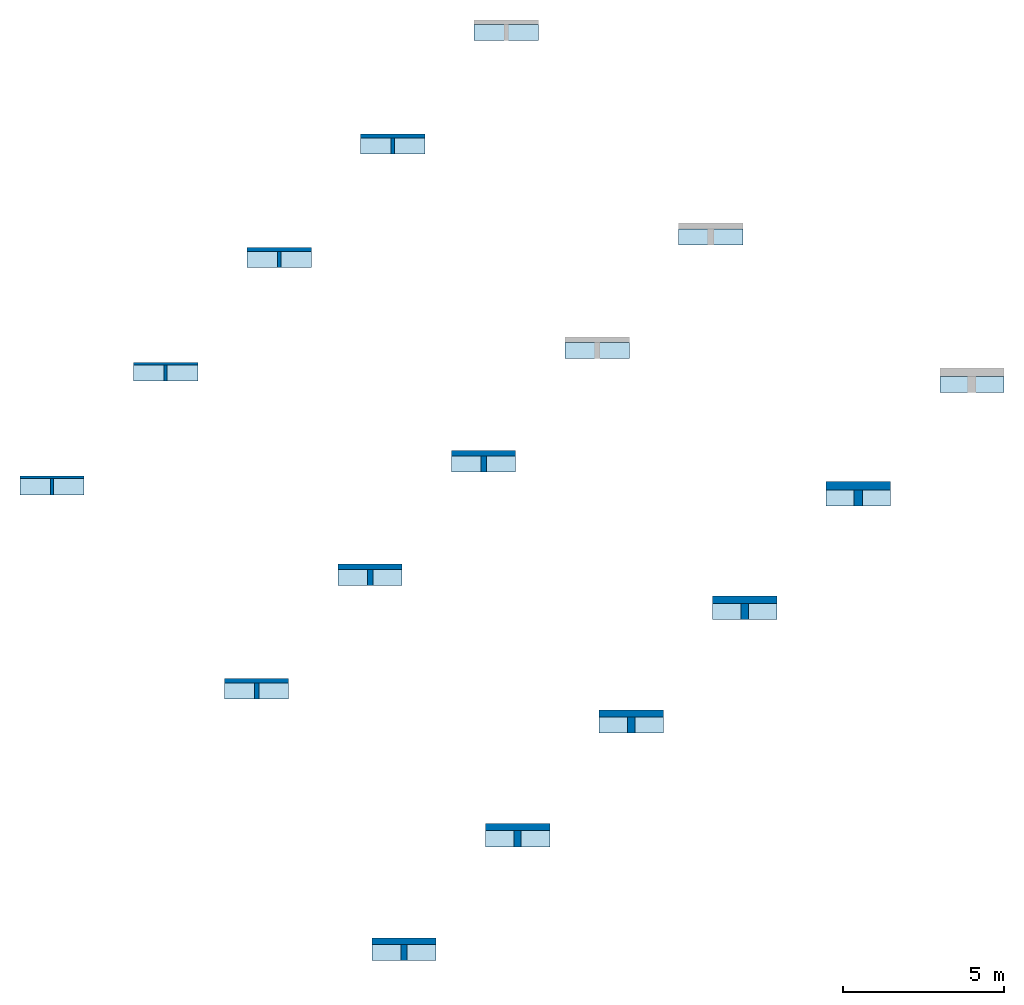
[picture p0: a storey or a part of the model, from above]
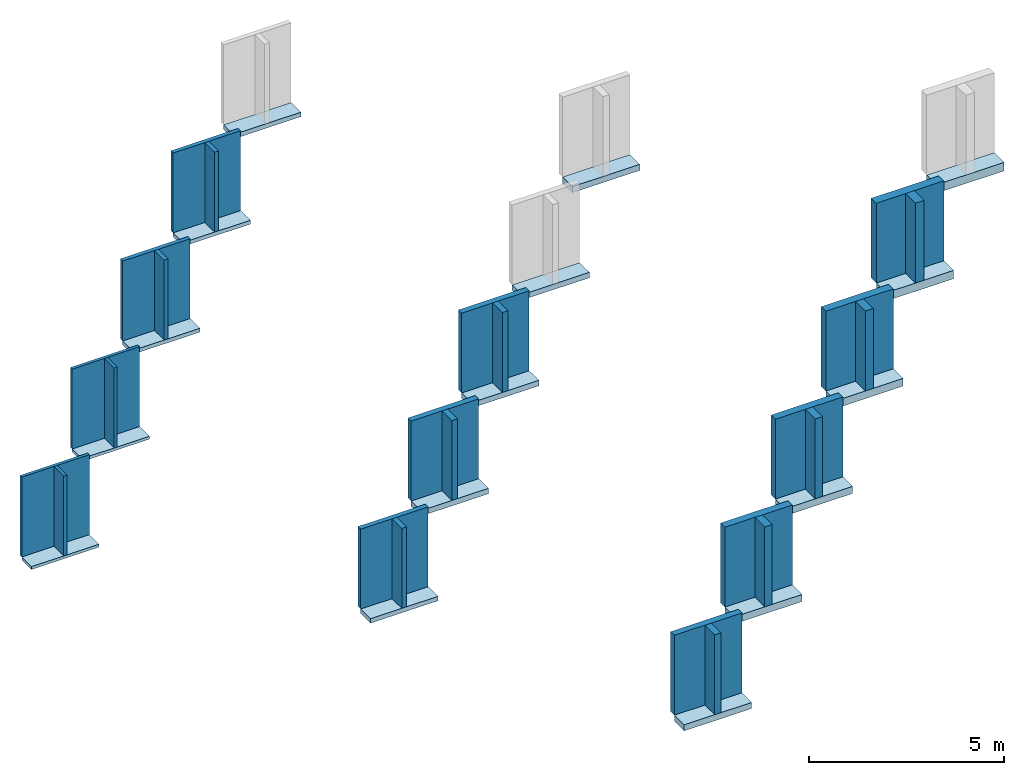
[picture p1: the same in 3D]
Properties of the parts of a building model (IFC2X3), part 1 of 3

# File
Description: ViewDefinition [CoordinationView_V2.0, QuantityTakeOffAddOnView]
Time: 2021-05-19T20:18:22
Written by: The EXPRESS Data Manager Version 5.02.0100.07 : 28 Aug 2013
Made in: 20190108_1515(x64) - Exporter 19.1.0.0 - Alternate UI 19.1.0.0
Comment: STEP Physical File produced by: The EXPRESS Data Manager Version 5.02.0100.07 : 28 Aug 2013 * Module: EDMstepFileFactory/EDMstandAlone * Creation date: Wed May 19 20:18:22 2021 * Host: lt-026 * Database: C:\Users\WF2BF~1.POE\AppData\Local\Temp\{9F13D511-4A9E-4208-AD03-301C394EC26A}\ifc * Database version: 5507 * Database creation date: Wed May 19 20:18:21 2021 * Schema: IFC2X3 * Model: DataRepository.ifc * Model creation date: Wed May 19 20:18:21 2021 * Header model: DataRepository.ifc_HeaderModel * Header model creation date: Wed May 19 20:18:21 2021 * EDMuser: sdai-user * EDMgroup: sdai-group * License ID and type: 5605 : Permanent license. Expiry date: * EDMstepFileFactory options: 020000

# IfcSite, Default
RefLatitude: 42, 24, 53, 508911; RefLongitude: -71, -15, -29, -58837; RefElevation: 0 mm
Other - Category: Project Information

# IfcBuilding
Pset_BuildingCommon - NumberOfStoreys: 2
Pset_ProductRequirements - Category: Project Information; sets with these values: 2

# IfcBuildingStorey: Level:Level 1, Begane grond
LongName: Begane grond; Elevation: 0 mm
Pset_AirSideSystemInformation - Name: Begane grond
Pset_ProductRequirements - Name: Begane grond; Category: Levels
Constraints - Elevation: 0 mm
Dimensions - Computation Height: 0 mm
Identity Data - Structural: no; Building Story: yes; Name: Begane grond
Other - Category: Levels; Family: Level: Level 1; Family and Type: Level: Level 1; Type: Level: Level 1; Type Id: Level: Level 1
Constraints(Type) - Elevation Base: Project Base Point
Graphics(Type) - Color: 0; Line Pattern: Solid; Line Weight: 1; Symbol at End 1 Default: no; Symbol at End 2 Default: yes
Identity Data(Type) - Type Name: Level 1
Other(Type) - Category: Levels; Family Name: Level

# IfcBuildingStorey: Level:NL_00_niveau, Lengte
LongName: Lengte; Elevation: 2500 mm
Other(Type) - Category: Levels; Family Name: Level
Pset_AirSideSystemInformation - Name: Lengte
Pset_ProductRequirements - Name: Lengte; Category: Levels
Constraints - Elevation: 2500 mm
Dimensions - Computation Height: 0 mm
Identity Data - Structural: no; Building Story: yes; Name: Lengte
Other - Category: Levels; Family: Level: NL_00_niveau; Family and Type: Level: NL_00_niveau; Type: Level: NL_00_niveau; Type Id: Level: NL_00_niveau
Constraints(Type) - Elevation Base: Project Base Point
Graphics(Type) - Line Weight: 1; Symbol at End 1 Default: no; Symbol at End 2 Default: yes; Color: 16711680; Line Pattern: NL_00_niveau; Symbol: NLRS_00_LAB_niveau bovenkant_gen_cadix: 1.8mm
Identity Data(Type) - Type Name: NL_00_niveau

# IfcRoof: Basic Roof:NLRS_27_RO_Naturoll 037_120x380x6500mm, Basic Roof:NLRS_27_RO_Naturoll 037_120x380x6500mm:13041
In: Lengte
Classification: 27 Daken (Uniformat)
Pset_ElementShading - Roughness: 304.8 mm
Pset_ManufacturerTypeInformation - Manufacturer: Knauf Insulation B.V.
Pset_ProductRequirements - Category: Roofs
Pset_QuantityTakeOff - Reference: NLRS_27_RO_Naturoll 037_120x380x6500mm
Pset_RoofCommon - IsExternal: yes; Reference: NLRS_27_RO_Naturoll 037_120x380x6500mm; ProjectedArea: 1 m2; TotalArea: 1 m2
Constraints - Related to Mass: no; Room Bounding: yes; Base Level: Level: Lengte; Base Offset From Level: 0 mm; Cutoff Offset: 0 mm
Construction - Fascia Depth: 0 mm; Rafter Cut: Plumb Cut; Maximum Ridge Height: 2620 mm
Dimensions - Area: 1 m2; Thickness: 120 mm; Volume: 0.12 m3
Other - Category: Roofs; Family: Basic Roof: NLRS_27_RO_Naturoll 037_120x380x6500mm; Family and Type: Basic Roof: NLRS_27_RO_Naturoll 037_120x380x6500mm; Type: Basic Roof: NLRS_27_RO_Naturoll 037_120x380x6500mm; Type Id: Basic Roof: NLRS_27_RO_Naturoll 037_120x380x6500mm
Phasing - Phase Created: New Construction
Analytical Properties(Type) - Roughness: 1; Thermal mass: 0; Absorptance: 0.1; Heat Transfer Coefficient (U): 0.291667; Thermal Resistance (R): 3.42857
Construction(Type) - Default Thickness: 120 mm
Graphics(Type) - Coarse Scale Fill Color: 0
Identity Data(Type) - Type Image: Raster image: Naturoll 037.jpg (3); Assembly Code: 27; Assembly Description: Daken; Description: Naturoll 037 - 120mm; Manufacturer: Knauf Insulation B.V.; Model: Naturoll 037 is een onbeklede glaswoldeken met ECOSE® Technology; Type Name: NLRS_27_RO_Naturoll 037_120x380x6500mm; URL: www.knaufinsulation.nl
Other(Type) - Category: Roofs; Family Name: Basic Roof

# IfcRoof: Basic Roof:NLRS_27_RO_Naturoll 037_120x580x6500mm, Basic Roof:NLRS_27_RO_Naturoll 037_120x580x6500mm:13066
In: Lengte
Classification: 27 Daken (Uniformat)
Pset_ElementShading - Roughness: 304.8 mm
Pset_ManufacturerTypeInformation - Manufacturer: Knauf Insulation B.V.
Pset_ProductRequirements - Category: Roofs
Pset_QuantityTakeOff - Reference: NLRS_27_RO_Naturoll 037_120x580x6500mm
Pset_RoofCommon - IsExternal: yes; Reference: NLRS_27_RO_Naturoll 037_120x580x6500mm; ProjectedArea: 1 m2; TotalArea: 1 m2
Constraints - Related to Mass: no; Room Bounding: yes; Base Level: Level: Lengte; Base Offset From Level: 0 mm; Cutoff Offset: 0 mm
Construction - Fascia Depth: 0 mm; Rafter Cut: Plumb Cut; Maximum Ridge Height: 2620 mm
Dimensions - Area: 1 m2; Thickness: 120 mm; Volume: 0.12 m3
Other - Category: Roofs; Family: Basic Roof: NLRS_27_RO_Naturoll 037_120x580x6500mm; Family and Type: Basic Roof: NLRS_27_RO_Naturoll 037_120x580x6500mm; Type: Basic Roof: NLRS_27_RO_Naturoll 037_120x580x6500mm; Type Id: Basic Roof: NLRS_27_RO_Naturoll 037_120x580x6500mm
Phasing - Phase Created: New Construction
Analytical Properties(Type) - Roughness: 1; Thermal mass: 0; Absorptance: 0.1; Heat Transfer Coefficient (U): 0.291667; Thermal Resistance (R): 3.42857
Construction(Type) - Default Thickness: 120 mm
Graphics(Type) - Coarse Scale Fill Color: 0
Identity Data(Type) - Type Image: Raster image: Naturoll 037.jpg (3); Assembly Code: 27; Assembly Description: Daken; Description: Naturoll 037 - 120mm; Manufacturer: Knauf Insulation B.V.; Model: Naturoll 037 is een onbeklede glaswoldeken met ECOSE® Technology; Type Name: NLRS_27_RO_Naturoll 037_120x580x6500mm; URL: www.knaufinsulation.nl
Other(Type) - Category: Roofs; Family Name: Basic Roof

# IfcRoof: Basic Roof:NLRS_27_RO_Naturoll 037_140x380x5600mm, Basic Roof:NLRS_27_RO_Naturoll 037_140x380x5600mm:13091
In: Lengte
Classification: 27 Daken (Uniformat)
Pset_ElementShading - Roughness: 304.8 mm
Pset_ManufacturerTypeInformation - Manufacturer: Knauf Insulation B.V.
Pset_ProductRequirements - Category: Roofs
Pset_QuantityTakeOff - Reference: NLRS_27_RO_Naturoll 037_140x380x5600mm
Pset_RoofCommon - IsExternal: yes; Reference: NLRS_27_RO_Naturoll 037_140x380x5600mm; ProjectedArea: 1 m2; TotalArea: 1 m2
Constraints - Related to Mass: no; Room Bounding: yes; Base Level: Level: Lengte; Base Offset From Level: 0 mm; Cutoff Offset: 0 mm
Construction - Fascia Depth: 0 mm; Rafter Cut: Plumb Cut; Maximum Ridge Height: 2640 mm
Dimensions - Area: 1 m2; Thickness: 140 mm; Volume: 0.14 m3
Other - Category: Roofs; Family: Basic Roof: NLRS_27_RO_Naturoll 037_140x380x5600mm; Family and Type: Basic Roof: NLRS_27_RO_Naturoll 037_140x380x5600mm; Type: Basic Roof: NLRS_27_RO_Naturoll 037_140x380x5600mm; Type Id: Basic Roof: NLRS_27_RO_Naturoll 037_140x380x5600mm
Phasing - Phase Created: New Construction
Analytical Properties(Type) - Roughness: 1; Thermal mass: 0; Thermal Resistance (R): 4; Absorptance: 0.1; Heat Transfer Coefficient (U): 0.25
Construction(Type) - Default Thickness: 140 mm
Graphics(Type) - Coarse Scale Fill Color: 0
Identity Data(Type) - Type Image: Raster image: Naturoll 037.jpg (3); Assembly Code: 27; Assembly Description: Daken; Description: Naturoll 037 - 140mm; Manufacturer: Knauf Insulation B.V.; Model: Naturoll 037 is een onbeklede glaswoldeken met ECOSE® Technology; Type Name: NLRS_27_RO_Naturoll 037_140x380x5600mm; URL: www.knaufinsulation.nl
Other(Type) - Category: Roofs; Family Name: Basic Roof

# IfcRoof: Basic Roof:NLRS_27_RO_Naturoll 037_140x580x5600mm, Basic Roof:NLRS_27_RO_Naturoll 037_140x580x5600mm:13324
In: Lengte
Classification: 27 Daken (Uniformat)
Pset_ElementShading - Roughness: 304.8 mm
Pset_ManufacturerTypeInformation - Manufacturer: Knauf Insulation B.V.
Pset_ProductRequirements - Category: Roofs
Pset_QuantityTakeOff - Reference: NLRS_27_RO_Naturoll 037_140x580x5600mm
Pset_RoofCommon - IsExternal: yes; Reference: NLRS_27_RO_Naturoll 037_140x580x5600mm; ProjectedArea: 1 m2; TotalArea: 1 m2
Constraints - Related to Mass: no; Room Bounding: yes; Base Level: Level: Lengte; Base Offset From Level: 0 mm; Cutoff Offset: 0 mm
Construction - Fascia Depth: 0 mm; Rafter Cut: Plumb Cut; Maximum Ridge Height: 2640 mm
Dimensions - Area: 1 m2; Thickness: 140 mm; Volume: 0.14 m3
Other - Category: Roofs; Family: Basic Roof: NLRS_27_RO_Naturoll 037_140x580x5600mm; Family and Type: Basic Roof: NLRS_27_RO_Naturoll 037_140x580x5600mm; Type: Basic Roof: NLRS_27_RO_Naturoll 037_140x580x5600mm; Type Id: Basic Roof: NLRS_27_RO_Naturoll 037_140x580x5600mm
Phasing - Phase Created: New Construction
Analytical Properties(Type) - Roughness: 1; Thermal mass: 0; Thermal Resistance (R): 4; Absorptance: 0.1; Heat Transfer Coefficient (U): 0.25
Construction(Type) - Default Thickness: 140 mm
Graphics(Type) - Coarse Scale Fill Color: 0
Identity Data(Type) - Type Image: Raster image: Naturoll 037.jpg (3); Assembly Code: 27; Assembly Description: Daken; Description: Naturoll 037 - 140mm; Manufacturer: Knauf Insulation B.V.; Model: Naturoll 037 is een onbeklede glaswoldeken met ECOSE® Technology; Type Name: NLRS_27_RO_Naturoll 037_140x580x5600mm; URL: www.knaufinsulation.nl
Other(Type) - Category: Roofs; Family Name: Basic Roof

# IfcRoof: Basic Roof:NLRS_27_RO_Naturoll 037_170x380x4600mm, Basic Roof:NLRS_27_RO_Naturoll 037_170x380x4600mm:13346
In: Lengte
Classification: 27 Daken (Uniformat)
Pset_ElementShading - Roughness: 304.8 mm
Pset_ManufacturerTypeInformation - Manufacturer: Knauf Insulation B.V.
Pset_ProductRequirements - Category: Roofs
Pset_QuantityTakeOff - Reference: NLRS_27_RO_Naturoll 037_170x380x4600mm
Pset_RoofCommon - IsExternal: yes; Reference: NLRS_27_RO_Naturoll 037_170x380x4600mm; ProjectedArea: 1 m2; TotalArea: 1 m2
Constraints - Related to Mass: no; Room Bounding: yes; Base Level: Level: Lengte; Base Offset From Level: 0 mm; Cutoff Offset: 0 mm
Construction - Fascia Depth: 0 mm; Rafter Cut: Plumb Cut; Maximum Ridge Height: 2670 mm
Dimensions - Area: 1 m2; Thickness: 170 mm; Volume: 0.17 m3
Other - Category: Roofs; Family: Basic Roof: NLRS_27_RO_Naturoll 037_170x380x4600mm; Family and Type: Basic Roof: NLRS_27_RO_Naturoll 037_170x380x4600mm; Type: Basic Roof: NLRS_27_RO_Naturoll 037_170x380x4600mm; Type Id: Basic Roof: NLRS_27_RO_Naturoll 037_170x380x4600mm
Phasing - Phase Created: New Construction
Analytical Properties(Type) - Roughness: 1; Thermal mass: 0; Absorptance: 0.1; Heat Transfer Coefficient (U): 0.205882; Thermal Resistance (R): 4.85714
Construction(Type) - Default Thickness: 170 mm
Graphics(Type) - Coarse Scale Fill Color: 0
Identity Data(Type) - Type Image: Raster image: Naturoll 037.jpg (3); Assembly Code: 27; Assembly Description: Daken; Description: Naturoll 037 - 170mm; Manufacturer: Knauf Insulation B.V.; Model: Naturoll 037 is een onbeklede glaswoldeken met ECOSE® Technology; Type Name: NLRS_27_RO_Naturoll 037_170x380x4600mm; URL: www.knaufinsulation.nl
Other(Type) - Category: Roofs; Family Name: Basic Roof

# IfcRoof: Basic Roof:NLRS_27_RO_Naturoll 037_170x580x4600mm, Basic Roof:NLRS_27_RO_Naturoll 037_170x580x4600mm:13368
In: Lengte
Classification: 27 Daken (Uniformat)
Pset_ElementShading - Roughness: 304.8 mm
Pset_ManufacturerTypeInformation - Manufacturer: Knauf Insulation B.V.
Pset_ProductRequirements - Category: Roofs
Pset_QuantityTakeOff - Reference: NLRS_27_RO_Naturoll 037_170x580x4600mm
Pset_RoofCommon - IsExternal: yes; Reference: NLRS_27_RO_Naturoll 037_170x580x4600mm; ProjectedArea: 1 m2; TotalArea: 1 m2
Constraints - Related to Mass: no; Room Bounding: yes; Base Level: Level: Lengte; Base Offset From Level: 0 mm; Cutoff Offset: 0 mm
Construction - Fascia Depth: 0 mm; Rafter Cut: Plumb Cut; Maximum Ridge Height: 2670 mm
Dimensions - Area: 1 m2; Thickness: 170 mm; Volume: 0.17 m3
Other - Category: Roofs; Family: Basic Roof: NLRS_27_RO_Naturoll 037_170x580x4600mm; Family and Type: Basic Roof: NLRS_27_RO_Naturoll 037_170x580x4600mm; Type: Basic Roof: NLRS_27_RO_Naturoll 037_170x580x4600mm; Type Id: Basic Roof: NLRS_27_RO_Naturoll 037_170x580x4600mm
Phasing - Phase Created: New Construction
Analytical Properties(Type) - Roughness: 1; Thermal mass: 0; Absorptance: 0.1; Heat Transfer Coefficient (U): 0.205882; Thermal Resistance (R): 4.85714
Construction(Type) - Default Thickness: 170 mm
Graphics(Type) - Coarse Scale Fill Color: 0
Identity Data(Type) - Type Image: Raster image: Naturoll 037.jpg (3); Assembly Code: 27; Assembly Description: Daken; Description: Naturoll 037 - 170mm; Manufacturer: Knauf Insulation B.V.; Model: Naturoll 037 is een onbeklede glaswoldeken met ECOSE® Technology; Type Name: NLRS_27_RO_Naturoll 037_170x580x4600mm; URL: www.knaufinsulation.nl
Other(Type) - Category: Roofs; Family Name: Basic Roof

# IfcRoof: Basic Roof:NLRS_27_RO_Naturoll 037_170x590x4600mm, Basic Roof:NLRS_27_RO_Naturoll 037_170x590x4600mm:13390
In: Lengte
Classification: 27 Daken (Uniformat)
Pset_ElementShading - Roughness: 304.8 mm
Pset_ManufacturerTypeInformation - Manufacturer: Knauf Insulation B.V.
Pset_ProductRequirements - Category: Roofs
Pset_QuantityTakeOff - Reference: NLRS_27_RO_Naturoll 037_170x590x4600mm
Pset_RoofCommon - IsExternal: yes; Reference: NLRS_27_RO_Naturoll 037_170x590x4600mm; ProjectedArea: 1 m2; TotalArea: 1 m2
Constraints - Related to Mass: no; Room Bounding: yes; Base Level: Level: Lengte; Base Offset From Level: 0 mm; Cutoff Offset: 0 mm
Construction - Fascia Depth: 0 mm; Rafter Cut: Plumb Cut; Maximum Ridge Height: 2670 mm
Dimensions - Area: 1 m2; Thickness: 170 mm; Volume: 0.17 m3
Other - Category: Roofs; Family: Basic Roof: NLRS_27_RO_Naturoll 037_170x590x4600mm; Family and Type: Basic Roof: NLRS_27_RO_Naturoll 037_170x590x4600mm; Type: Basic Roof: NLRS_27_RO_Naturoll 037_170x590x4600mm; Type Id: Basic Roof: NLRS_27_RO_Naturoll 037_170x590x4600mm
Phasing - Phase Created: New Construction
Analytical Properties(Type) - Roughness: 1; Thermal mass: 0; Absorptance: 0.1; Heat Transfer Coefficient (U): 0.205882; Thermal Resistance (R): 4.85714
Construction(Type) - Default Thickness: 170 mm
Graphics(Type) - Coarse Scale Fill Color: 0
Identity Data(Type) - Type Image: Raster image: Naturoll 037.jpg (3); Assembly Code: 27; Assembly Description: Daken; Description: Naturoll 037 - 170mm; Manufacturer: Knauf Insulation B.V.; Model: Naturoll 037 is een onbeklede glaswoldeken met ECOSE® Technology; Type Name: NLRS_27_RO_Naturoll 037_170x590x4600mm; URL: www.knaufinsulation.nl
Other(Type) - Category: Roofs; Family Name: Basic Roof

# IfcRoof: Basic Roof:NLRS_27_RO_Naturoll 037_190x380x4100mm, Basic Roof:NLRS_27_RO_Naturoll 037_190x380x4100mm:13412
In: Lengte
Classification: 27 Daken (Uniformat)
Pset_ElementShading - Roughness: 304.8 mm
Pset_ManufacturerTypeInformation - Manufacturer: Knauf Insulation B.V.
Pset_ProductRequirements - Category: Roofs
Pset_QuantityTakeOff - Reference: NLRS_27_RO_Naturoll 037_190x380x4100mm
Pset_RoofCommon - IsExternal: yes; Reference: NLRS_27_RO_Naturoll 037_190x380x4100mm; ProjectedArea: 1 m2; TotalArea: 1 m2
Constraints - Related to Mass: no; Room Bounding: yes; Base Level: Level: Lengte; Base Offset From Level: 0 mm; Cutoff Offset: 0 mm
Construction - Fascia Depth: 0 mm; Rafter Cut: Plumb Cut; Maximum Ridge Height: 2690 mm
Dimensions - Area: 1 m2; Thickness: 190 mm; Volume: 0.19 m3
Other - Category: Roofs; Family: Basic Roof: NLRS_27_RO_Naturoll 037_190x380x4100mm; Family and Type: Basic Roof: NLRS_27_RO_Naturoll 037_190x380x4100mm; Type: Basic Roof: NLRS_27_RO_Naturoll 037_190x380x4100mm; Type Id: Basic Roof: NLRS_27_RO_Naturoll 037_190x380x4100mm
Phasing - Phase Created: New Construction
Analytical Properties(Type) - Roughness: 1; Thermal mass: 0; Absorptance: 0.1; Heat Transfer Coefficient (U): 0.184211; Thermal Resistance (R): 5.42857
Construction(Type) - Default Thickness: 190 mm
Graphics(Type) - Coarse Scale Fill Color: 0
Identity Data(Type) - Type Image: Raster image: Naturoll 037.jpg (3); Assembly Code: 27; Assembly Description: Daken; Description: Naturoll 037 - 190mm; Manufacturer: Knauf Insulation B.V.; Model: Naturoll 037 is een onbeklede glaswoldeken met ECOSE® Technology; Type Name: NLRS_27_RO_Naturoll 037_190x380x4100mm; URL: www.knaufinsulation.nl
Other(Type) - Category: Roofs; Family Name: Basic Roof

# IfcRoof: Basic Roof:NLRS_27_RO_Naturoll 037_190x590x4100mm, Basic Roof:NLRS_27_RO_Naturoll 037_190x590x4100mm:13511
In: Lengte
Classification: 27 Daken (Uniformat)
Pset_ElementShading - Roughness: 304.8 mm
Pset_ManufacturerTypeInformation - Manufacturer: Knauf Insulation B.V.
Pset_ProductRequirements - Category: Roofs
Pset_QuantityTakeOff - Reference: NLRS_27_RO_Naturoll 037_190x590x4100mm
Pset_RoofCommon - IsExternal: yes; Reference: NLRS_27_RO_Naturoll 037_190x590x4100mm; ProjectedArea: 1 m2; TotalArea: 1 m2
Constraints - Related to Mass: no; Room Bounding: yes; Base Level: Level: Lengte; Base Offset From Level: 0 mm; Cutoff Offset: 0 mm
Construction - Fascia Depth: 0 mm; Rafter Cut: Plumb Cut; Maximum Ridge Height: 2690 mm
Dimensions - Area: 1 m2; Thickness: 190 mm; Volume: 0.19 m3
Other - Category: Roofs; Family: Basic Roof: NLRS_27_RO_Naturoll 037_190x590x4100mm; Family and Type: Basic Roof: NLRS_27_RO_Naturoll 037_190x590x4100mm; Type: Basic Roof: NLRS_27_RO_Naturoll 037_190x590x4100mm; Type Id: Basic Roof: NLRS_27_RO_Naturoll 037_190x590x4100mm
Phasing - Phase Created: New Construction
Analytical Properties(Type) - Roughness: 1; Thermal mass: 0; Absorptance: 0.1; Heat Transfer Coefficient (U): 0.184211; Thermal Resistance (R): 5.42857
Construction(Type) - Default Thickness: 190 mm
Graphics(Type) - Coarse Scale Fill Color: 0
Identity Data(Type) - Type Image: Raster image: Naturoll 037.jpg (3); Assembly Code: 27; Assembly Description: Daken; Description: Naturoll 037 - 190mm; Manufacturer: Knauf Insulation B.V.; Model: Naturoll 037 is een onbeklede glaswoldeken met ECOSE® Technology; Type Name: NLRS_27_RO_Naturoll 037_190x590x4100mm; URL: www.knaufinsulation.nl
Other(Type) - Category: Roofs; Family Name: Basic Roof

# IfcRoof: Basic Roof:NLRS_27_RO_Naturoll 037_220x580x3500mm, Basic Roof:NLRS_27_RO_Naturoll 037_220x580x3500mm:13531
In: Lengte
Classification: 27 Daken (Uniformat)
Pset_ElementShading - Roughness: 304.8 mm
Pset_ManufacturerTypeInformation - Manufacturer: Knauf Insulation B.V.
Pset_ProductRequirements - Category: Roofs
Pset_QuantityTakeOff - Reference: NLRS_27_RO_Naturoll 037_220x580x3500mm
Pset_RoofCommon - IsExternal: yes; Reference: NLRS_27_RO_Naturoll 037_220x580x3500mm; ProjectedArea: 1 m2; TotalArea: 1 m2
Constraints - Related to Mass: no; Room Bounding: yes; Base Level: Level: Lengte; Base Offset From Level: 0 mm; Cutoff Offset: 0 mm
Construction - Fascia Depth: 0 mm; Rafter Cut: Plumb Cut; Maximum Ridge Height: 2720 mm
Dimensions - Area: 1 m2; Thickness: 220 mm; Volume: 0.22 m3
Other - Category: Roofs; Family: Basic Roof: NLRS_27_RO_Naturoll 037_220x580x3500mm; Family and Type: Basic Roof: NLRS_27_RO_Naturoll 037_220x580x3500mm; Type: Basic Roof: NLRS_27_RO_Naturoll 037_220x580x3500mm; Type Id: Basic Roof: NLRS_27_RO_Naturoll 037_220x580x3500mm
Phasing - Phase Created: New Construction
Analytical Properties(Type) - Roughness: 1; Thermal mass: 0; Absorptance: 0.1; Heat Transfer Coefficient (U): 0.159091; Thermal Resistance (R): 6.28571
Construction(Type) - Default Thickness: 220 mm
Graphics(Type) - Coarse Scale Fill Color: 0
Identity Data(Type) - Type Image: Raster image: Naturoll 037.jpg (3); Assembly Code: 27; Assembly Description: Daken; Description: Naturoll 037 - 220mm; Manufacturer: Knauf Insulation B.V.; Model: Naturoll 037 is een onbeklede glaswoldeken met ECOSE® Technology; Type Name: NLRS_27_RO_Naturoll 037_220x580x3500mm; URL: www.knaufinsulation.nl
Other(Type) - Category: Roofs; Family Name: Basic Roof

# IfcRoof: Basic Roof:NLRS_27_RO_Naturoll 037_220x590x3500mm, Basic Roof:NLRS_27_RO_Naturoll 037_220x590x3500mm:13551
In: Lengte
Classification: 27 Daken (Uniformat)
Pset_ElementShading - Roughness: 304.8 mm
Pset_ManufacturerTypeInformation - Manufacturer: Knauf Insulation B.V.
Pset_ProductRequirements - Category: Roofs
Pset_QuantityTakeOff - Reference: NLRS_27_RO_Naturoll 037_220x590x3500mm
Pset_RoofCommon - IsExternal: yes; Reference: NLRS_27_RO_Naturoll 037_220x590x3500mm; ProjectedArea: 1 m2; TotalArea: 1 m2
Constraints - Related to Mass: no; Room Bounding: yes; Base Level: Level: Lengte; Base Offset From Level: 0 mm; Cutoff Offset: 0 mm
Construction - Fascia Depth: 0 mm; Rafter Cut: Plumb Cut; Maximum Ridge Height: 2720 mm
Dimensions - Area: 1 m2; Thickness: 220 mm; Volume: 0.22 m3
Other - Category: Roofs; Family: Basic Roof: NLRS_27_RO_Naturoll 037_220x590x3500mm; Family and Type: Basic Roof: NLRS_27_RO_Naturoll 037_220x590x3500mm; Type: Basic Roof: NLRS_27_RO_Naturoll 037_220x590x3500mm; Type Id: Basic Roof: NLRS_27_RO_Naturoll 037_220x590x3500mm
Phasing - Phase Created: New Construction
Analytical Properties(Type) - Roughness: 1; Thermal mass: 0; Absorptance: 0.1; Heat Transfer Coefficient (U): 0.159091; Thermal Resistance (R): 6.28571
Construction(Type) - Default Thickness: 220 mm
Graphics(Type) - Coarse Scale Fill Color: 0
Identity Data(Type) - Type Image: Raster image: Naturoll 037.jpg (3); Assembly Code: 27; Assembly Description: Daken; Description: Naturoll 037 - 220mm; Manufacturer: Knauf Insulation B.V.; Model: Naturoll 037 is een onbeklede glaswoldeken met ECOSE® Technology; Type Name: NLRS_27_RO_Naturoll 037_220x590x3500mm; URL: www.knaufinsulation.nl
Other(Type) - Category: Roofs; Family Name: Basic Roof

# IfcRoof: Basic Roof:NLRS_27_RO_Naturoll 037_240x590x3250mm, Basic Roof:NLRS_27_RO_Naturoll 037_240x590x3250mm:13571
In: Lengte
Classification: 27 Daken (Uniformat)
Pset_ElementShading - Roughness: 304.8 mm
Pset_ManufacturerTypeInformation - Manufacturer: Knauf Insulation B.V.
Pset_ProductRequirements - Category: Roofs
Pset_QuantityTakeOff - Reference: NLRS_27_RO_Naturoll 037_240x590x3250mm
Pset_RoofCommon - IsExternal: yes; Reference: NLRS_27_RO_Naturoll 037_240x590x3250mm; ProjectedArea: 1 m2; TotalArea: 1 m2
Constraints - Related to Mass: no; Room Bounding: yes; Base Level: Level: Lengte; Base Offset From Level: 0 mm; Cutoff Offset: 0 mm
Construction - Fascia Depth: 0 mm; Rafter Cut: Plumb Cut; Maximum Ridge Height: 2740 mm
Dimensions - Area: 1 m2; Thickness: 240 mm; Volume: 0.24 m3
Other - Category: Roofs; Family: Basic Roof: NLRS_27_RO_Naturoll 037_240x590x3250mm; Family and Type: Basic Roof: NLRS_27_RO_Naturoll 037_240x590x3250mm; Type: Basic Roof: NLRS_27_RO_Naturoll 037_240x590x3250mm; Type Id: Basic Roof: NLRS_27_RO_Naturoll 037_240x590x3250mm
Phasing - Phase Created: New Construction
Analytical Properties(Type) - Roughness: 1; Thermal mass: 0; Absorptance: 0.1; Heat Transfer Coefficient (U): 0.145833; Thermal Resistance (R): 6.85714
Construction(Type) - Default Thickness: 240 mm
Graphics(Type) - Coarse Scale Fill Color: 0
Identity Data(Type) - Type Image: Raster image: Naturoll 037.jpg (3); Assembly Code: 27; Assembly Description: Daken; Description: Naturoll 037 - 240mm; Manufacturer: Knauf Insulation B.V.; Model: Naturoll 037 is een onbeklede glaswoldeken met ECOSE® Technology; Type Name: NLRS_27_RO_Naturoll 037_240x590x3250mm; URL: www.knaufinsulation.nl
Other(Type) - Category: Roofs; Family Name: Basic Roof

# IfcRoof: Basic Roof:NLRS_27_RO_Naturoll 037_260x580x3000mm, Basic Roof:NLRS_27_RO_Naturoll 037_260x580x3000mm:13591
In: Lengte
Classification: 27 Daken (Uniformat)
Pset_ElementShading - Roughness: 304.8 mm
Pset_ManufacturerTypeInformation - Manufacturer: Knauf Insulation B.V.
Pset_ProductRequirements - Category: Roofs
Pset_QuantityTakeOff - Reference: NLRS_27_RO_Naturoll 037_260x580x3000mm
Pset_RoofCommon - IsExternal: yes; Reference: NLRS_27_RO_Naturoll 037_260x580x3000mm; ProjectedArea: 1 m2; TotalArea: 1 m2
Constraints - Related to Mass: no; Room Bounding: yes; Base Level: Level: Lengte; Base Offset From Level: 0 mm; Cutoff Offset: 0 mm
Construction - Fascia Depth: 0 mm; Rafter Cut: Plumb Cut; Maximum Ridge Height: 2760 mm
Dimensions - Area: 1 m2; Thickness: 260 mm; Volume: 0.26 m3
Other - Category: Roofs; Family: Basic Roof: NLRS_27_RO_Naturoll 037_260x580x3000mm; Family and Type: Basic Roof: NLRS_27_RO_Naturoll 037_260x580x3000mm; Type: Basic Roof: NLRS_27_RO_Naturoll 037_260x580x3000mm; Type Id: Basic Roof: NLRS_27_RO_Naturoll 037_260x580x3000mm
Phasing - Phase Created: New Construction
Analytical Properties(Type) - Roughness: 1; Thermal mass: 0; Absorptance: 0.1; Heat Transfer Coefficient (U): 0.134615; Thermal Resistance (R): 7.42857
Construction(Type) - Default Thickness: 260 mm
Graphics(Type) - Coarse Scale Fill Color: 0
Identity Data(Type) - Type Image: Raster image: Naturoll 037.jpg (3); Assembly Code: 27; Assembly Description: Daken; Description: Naturoll 037 - 260mm; Manufacturer: Knauf Insulation B.V.; Model: Naturoll 037 is een onbeklede glaswoldeken met ECOSE® Technology; Type Name: NLRS_27_RO_Naturoll 037_260x580x3000mm; URL: www.knaufinsulation.nl
Other(Type) - Category: Roofs; Family Name: Basic Roof

# IfcRoof: Basic Roof:NLRS_27_RO_Naturoll 037_265x590x3000mm, Basic Roof:NLRS_27_RO_Naturoll 037_265x590x3000mm:13729
In: Lengte
Classification: 27 Daken (Uniformat)
Pset_ElementShading - Roughness: 304.8 mm
Pset_ManufacturerTypeInformation - Manufacturer: Knauf Insulation B.V.
Pset_ProductRequirements - Category: Roofs
Pset_QuantityTakeOff - Reference: NLRS_27_RO_Naturoll 037_265x590x3000mm
Pset_RoofCommon - IsExternal: yes; Reference: NLRS_27_RO_Naturoll 037_265x590x3000mm; ProjectedArea: 1 m2; TotalArea: 1 m2
Constraints - Related to Mass: no; Room Bounding: yes; Base Level: Level: Lengte; Base Offset From Level: 0 mm; Cutoff Offset: 0 mm
Construction - Fascia Depth: 0 mm; Rafter Cut: Plumb Cut; Maximum Ridge Height: 2765 mm
Dimensions - Area: 1 m2; Thickness: 265 mm; Volume: 0.265 m3
Other - Category: Roofs; Family: Basic Roof: NLRS_27_RO_Naturoll 037_265x590x3000mm; Family and Type: Basic Roof: NLRS_27_RO_Naturoll 037_265x590x3000mm; Type: Basic Roof: NLRS_27_RO_Naturoll 037_265x590x3000mm; Type Id: Basic Roof: NLRS_27_RO_Naturoll 037_265x590x3000mm
Phasing - Phase Created: New Construction
Analytical Properties(Type) - Roughness: 1; Thermal mass: 0; Absorptance: 0.1; Heat Transfer Coefficient (U): 0.132075; Thermal Resistance (R): 7.57143
Construction(Type) - Default Thickness: 265 mm
Graphics(Type) - Coarse Scale Fill Color: 0
Identity Data(Type) - Type Image: Raster image: Naturoll 037.jpg (3); Assembly Code: 27; Assembly Description: Daken; Description: Naturoll 037 - 265mm; Manufacturer: Knauf Insulation B.V.; Model: Naturoll 037 is een onbeklede glaswoldeken met ECOSE® Technology; Type Name: NLRS_27_RO_Naturoll 037_265x590x3000mm; URL: www.knaufinsulation.nl
Other(Type) - Category: Roofs; Family Name: Basic Roof

# IfcRoof: Basic Roof:NLRS_27_RO_Naturoll 037_90x380x8200mm, Basic Roof:NLRS_27_RO_Naturoll 037_90x380x8200mm:12720
In: Lengte
Classification: 27 Daken (Uniformat)
Pset_ElementShading - Roughness: 304.8 mm
Pset_ManufacturerTypeInformation - Manufacturer: Knauf Insulation B.V.
Pset_ProductRequirements - Category: Roofs
Pset_QuantityTakeOff - Reference: NLRS_27_RO_Naturoll 037_90x380x8200mm
Pset_RoofCommon - IsExternal: yes; Reference: NLRS_27_RO_Naturoll 037_90x380x8200mm; ProjectedArea: 1 m2; TotalArea: 1 m2
Constraints - Related to Mass: no; Room Bounding: yes; Base Level: Level: Lengte; Base Offset From Level: 0 mm; Cutoff Offset: 0 mm
Construction - Fascia Depth: 0 mm; Maximum Ridge Height: 2590 mm; Rafter Cut: Plumb Cut
Dimensions - Area: 1 m2; Thickness: 90 mm; Volume: 0.09 m3
Other - Category: Roofs; Family: Basic Roof: NLRS_27_RO_Naturoll 037_90x380x8200mm; Family and Type: Basic Roof: NLRS_27_RO_Naturoll 037_90x380x8200mm; Type: Basic Roof: NLRS_27_RO_Naturoll 037_90x380x8200mm; Type Id: Basic Roof: NLRS_27_RO_Naturoll 037_90x380x8200mm
Phasing - Phase Created: New Construction
Analytical Properties(Type) - Roughness: 1; Thermal mass: 0; Absorptance: 0.1; Heat Transfer Coefficient (U): 0.388889; Thermal Resistance (R): 2.57143
Construction(Type) - Default Thickness: 90 mm
Graphics(Type) - Coarse Scale Fill Color: 0
Identity Data(Type) - Type Image: Raster image: Naturoll 037.jpg (3); Assembly Code: 27; Assembly Description: Daken; Description: Naturoll 037 - 90mm; Manufacturer: Knauf Insulation B.V.; Model: Naturoll 037 is een onbeklede glaswoldeken met ECOSE® Technology; Type Name: NLRS_27_RO_Naturoll 037_90x380x8200mm; URL: www.knaufinsulation.nl
Other(Type) - Category: Roofs; Family Name: Basic Roof

# IfcRoof: Basic Roof:NLRS_27_RO_Naturoll 037_90x580x8200mm, Basic Roof:NLRS_27_RO_Naturoll 037_90x580x8200mm:12989
In: Lengte
Classification: 27 Daken (Uniformat)
Pset_ElementShading - Roughness: 304.8 mm
Pset_ManufacturerTypeInformation - Manufacturer: Knauf Insulation B.V.
Pset_ProductRequirements - Category: Roofs
Pset_QuantityTakeOff - Reference: NLRS_27_RO_Naturoll 037_90x580x8200mm
Pset_RoofCommon - IsExternal: yes; Reference: NLRS_27_RO_Naturoll 037_90x580x8200mm; ProjectedArea: 1 m2; TotalArea: 1 m2
Constraints - Related to Mass: no; Room Bounding: yes; Base Level: Level: Lengte; Base Offset From Level: 0 mm; Cutoff Offset: 0 mm
Construction - Fascia Depth: 0 mm; Rafter Cut: Plumb Cut; Maximum Ridge Height: 2590 mm
Dimensions - Area: 1 m2; Thickness: 90 mm; Volume: 0.09 m3
Other - Category: Roofs; Family: Basic Roof: NLRS_27_RO_Naturoll 037_90x580x8200mm; Family and Type: Basic Roof: NLRS_27_RO_Naturoll 037_90x580x8200mm; Type: Basic Roof: NLRS_27_RO_Naturoll 037_90x580x8200mm; Type Id: Basic Roof: NLRS_27_RO_Naturoll 037_90x580x8200mm
Phasing - Phase Created: New Construction
Analytical Properties(Type) - Roughness: 1; Thermal mass: 0; Absorptance: 0.1; Heat Transfer Coefficient (U): 0.388889; Thermal Resistance (R): 2.57143
Construction(Type) - Default Thickness: 90 mm
Graphics(Type) - Coarse Scale Fill Color: 0
Identity Data(Type) - Type Image: Raster image: Naturoll 037.jpg (3); Assembly Code: 27; Assembly Description: Daken; Description: Naturoll 037 - 90mm; Manufacturer: Knauf Insulation B.V.; Model: Naturoll 037 is een onbeklede glaswoldeken met ECOSE® Technology; Type Name: NLRS_27_RO_Naturoll 037_90x580x8200mm; URL: www.knaufinsulation.nl
Other(Type) - Category: Roofs; Family Name: Basic Roof

# IfcSlab: Basic Roof:NLRS_27_RO_Naturoll 037_120x380x6500mm, Basic Roof:NLRS_27_RO_Naturoll 037_120x380x6500mm:13041
In: Lengte
PredefinedType: ROOF; Classification: 27 Daken (Uniformat); Material: Knauf Insulation_Ecose® glaswol_naturoll 037 120 mm
Pset_ElementShading - Roughness: 304.8 mm
Pset_ManufacturerTypeInformation - Manufacturer: Knauf Insulation B.V.
Pset_ProductRequirements - Category: Roofs
Pset_QuantityTakeOff - Reference: NLRS_27_RO_Naturoll 037_120x380x6500mm
Pset_ReinforcementBarPitchOfSlab - Description: Naturoll 037 - 120mm; Reference: NLRS_27_RO_Naturoll 037_120x380x6500mm
Pset_SlabCommon - PitchAngle: 0 deg; IsExternal: yes; Reference: NLRS_27_RO_Naturoll 037_120x380x6500mm; ThermalTransmittance: 0.291667 kg/K/s3
BaseQuantities - GrossArea: 0.092903 m2; NetArea: 2.6 m2; GrossVolume: 11.1484 m3; NetVolume: 0.12 m3; Perimeter: 5000 mm; Width: 120 mm

# IfcSlab: Basic Roof:NLRS_27_RO_Naturoll 037_120x580x6500mm, Basic Roof:NLRS_27_RO_Naturoll 037_120x580x6500mm:13066
In: Lengte
PredefinedType: ROOF; Classification: 27 Daken (Uniformat); Material: Knauf Insulation_Ecose® glaswol_naturoll 037 120 mm
Pset_ElementShading - Roughness: 304.8 mm
Pset_ManufacturerTypeInformation - Manufacturer: Knauf Insulation B.V.
Pset_ProductRequirements - Category: Roofs
Pset_QuantityTakeOff - Reference: NLRS_27_RO_Naturoll 037_120x580x6500mm
Pset_ReinforcementBarPitchOfSlab - Description: Naturoll 037 - 120mm; Reference: NLRS_27_RO_Naturoll 037_120x580x6500mm
Pset_SlabCommon - PitchAngle: 0 deg; IsExternal: yes; Reference: NLRS_27_RO_Naturoll 037_120x580x6500mm; ThermalTransmittance: 0.291667 kg/K/s3
BaseQuantities - GrossArea: 0.092903 m2; NetArea: 2.6 m2; GrossVolume: 11.1484 m3; NetVolume: 0.12 m3; Perimeter: 5000 mm; Width: 120 mm

# IfcSlab: Basic Roof:NLRS_27_RO_Naturoll 037_140x380x5600mm, Basic Roof:NLRS_27_RO_Naturoll 037_140x380x5600mm:13091
In: Lengte
PredefinedType: ROOF; Classification: 27 Daken (Uniformat); Material: Knauf Insulation_Ecose® glaswol_naturoll 037 140 mm
Pset_ElementShading - Roughness: 304.8 mm
Pset_ManufacturerTypeInformation - Manufacturer: Knauf Insulation B.V.
Pset_ProductRequirements - Category: Roofs
Pset_QuantityTakeOff - Reference: NLRS_27_RO_Naturoll 037_140x380x5600mm
Pset_ReinforcementBarPitchOfSlab - Description: Naturoll 037 - 140mm; Reference: NLRS_27_RO_Naturoll 037_140x380x5600mm
Pset_SlabCommon - PitchAngle: 0 deg; IsExternal: yes; ThermalTransmittance: 0.25 kg/K/s3; Reference: NLRS_27_RO_Naturoll 037_140x380x5600mm
BaseQuantities - GrossArea: 0.092903 m2; NetArea: 2.7 m2; GrossVolume: 13.0064 m3; NetVolume: 0.14 m3; Perimeter: 5000 mm; Width: 140 mm

# IfcSlab: Basic Roof:NLRS_27_RO_Naturoll 037_140x580x5600mm, Basic Roof:NLRS_27_RO_Naturoll 037_140x580x5600mm:13324
In: Lengte
PredefinedType: ROOF; Classification: 27 Daken (Uniformat); Material: Knauf Insulation_Ecose® glaswol_naturoll 037 140 mm
Pset_ElementShading - Roughness: 304.8 mm
Pset_ManufacturerTypeInformation - Manufacturer: Knauf Insulation B.V.
Pset_ProductRequirements - Category: Roofs
Pset_QuantityTakeOff - Reference: NLRS_27_RO_Naturoll 037_140x580x5600mm
Pset_ReinforcementBarPitchOfSlab - Description: Naturoll 037 - 140mm; Reference: NLRS_27_RO_Naturoll 037_140x580x5600mm
Pset_SlabCommon - PitchAngle: 0 deg; IsExternal: yes; ThermalTransmittance: 0.25 kg/K/s3; Reference: NLRS_27_RO_Naturoll 037_140x580x5600mm
BaseQuantities - GrossArea: 0.092903 m2; NetArea: 2.7 m2; GrossVolume: 13.0064 m3; NetVolume: 0.14 m3; Perimeter: 5000 mm; Width: 140 mm

# IfcSlab: Basic Roof:NLRS_27_RO_Naturoll 037_170x380x4600mm, Basic Roof:NLRS_27_RO_Naturoll 037_170x380x4600mm:13346
In: Lengte
PredefinedType: ROOF; Classification: 27 Daken (Uniformat); Material: Knauf Insulation_Ecose® glaswol_naturoll 037 170 mm
Pset_ElementShading - Roughness: 304.8 mm
Pset_ManufacturerTypeInformation - Manufacturer: Knauf Insulation B.V.
Pset_ProductRequirements - Category: Roofs
Pset_QuantityTakeOff - Reference: NLRS_27_RO_Naturoll 037_170x380x4600mm
Pset_ReinforcementBarPitchOfSlab - Description: Naturoll 037 - 170mm; Reference: NLRS_27_RO_Naturoll 037_170x380x4600mm
Pset_SlabCommon - PitchAngle: 0 deg; IsExternal: yes; Reference: NLRS_27_RO_Naturoll 037_170x380x4600mm; ThermalTransmittance: 0.205882 kg/K/s3
BaseQuantities - GrossArea: 0.092903 m2; NetArea: 2.85 m2; GrossVolume: 15.7935 m3; NetVolume: 0.17 m3; Perimeter: 5000 mm; Width: 170 mm

# IfcSlab: Basic Roof:NLRS_27_RO_Naturoll 037_170x580x4600mm, Basic Roof:NLRS_27_RO_Naturoll 037_170x580x4600mm:13368
In: Lengte
PredefinedType: ROOF; Classification: 27 Daken (Uniformat); Material: Knauf Insulation_Ecose® glaswol_naturoll 037 170 mm
Pset_ElementShading - Roughness: 304.8 mm
Pset_ManufacturerTypeInformation - Manufacturer: Knauf Insulation B.V.
Pset_ProductRequirements - Category: Roofs
Pset_QuantityTakeOff - Reference: NLRS_27_RO_Naturoll 037_170x580x4600mm
Pset_ReinforcementBarPitchOfSlab - Description: Naturoll 037 - 170mm; Reference: NLRS_27_RO_Naturoll 037_170x580x4600mm
Pset_SlabCommon - PitchAngle: 0 deg; IsExternal: yes; Reference: NLRS_27_RO_Naturoll 037_170x580x4600mm; ThermalTransmittance: 0.205882 kg/K/s3
BaseQuantities - GrossArea: 0.092903 m2; NetArea: 2.85 m2; GrossVolume: 15.7935 m3; NetVolume: 0.17 m3; Perimeter: 5000 mm; Width: 170 mm

# IfcSlab: Basic Roof:NLRS_27_RO_Naturoll 037_170x590x4600mm, Basic Roof:NLRS_27_RO_Naturoll 037_170x590x4600mm:13390
In: Lengte
PredefinedType: ROOF; Classification: 27 Daken (Uniformat); Material: Knauf Insulation_Ecose® glaswol_naturoll 037 170 mm
Pset_ElementShading - Roughness: 304.8 mm
Pset_ManufacturerTypeInformation - Manufacturer: Knauf Insulation B.V.
Pset_ProductRequirements - Category: Roofs
Pset_QuantityTakeOff - Reference: NLRS_27_RO_Naturoll 037_170x590x4600mm
Pset_ReinforcementBarPitchOfSlab - Description: Naturoll 037 - 170mm; Reference: NLRS_27_RO_Naturoll 037_170x590x4600mm
Pset_SlabCommon - PitchAngle: 0 deg; IsExternal: yes; Reference: NLRS_27_RO_Naturoll 037_170x590x4600mm; ThermalTransmittance: 0.205882 kg/K/s3
BaseQuantities - GrossArea: 0.092903 m2; NetArea: 2.85 m2; GrossVolume: 15.7935 m3; NetVolume: 0.17 m3; Perimeter: 5000 mm; Width: 170 mm

# IfcSlab: Basic Roof:NLRS_27_RO_Naturoll 037_190x380x4100mm, Basic Roof:NLRS_27_RO_Naturoll 037_190x380x4100mm:13412
In: Lengte
PredefinedType: ROOF; Classification: 27 Daken (Uniformat); Material: Knauf Insulation_Ecose® glaswol_naturoll 037 190 mm
Pset_ElementShading - Roughness: 304.8 mm
Pset_ManufacturerTypeInformation - Manufacturer: Knauf Insulation B.V.
Pset_ProductRequirements - Category: Roofs
Pset_QuantityTakeOff - Reference: NLRS_27_RO_Naturoll 037_190x380x4100mm
Pset_ReinforcementBarPitchOfSlab - Description: Naturoll 037 - 190mm; Reference: NLRS_27_RO_Naturoll 037_190x380x4100mm
Pset_SlabCommon - PitchAngle: 0 deg; IsExternal: yes; Reference: NLRS_27_RO_Naturoll 037_190x380x4100mm; ThermalTransmittance: 0.184211 kg/K/s3
BaseQuantities - GrossArea: 0.092903 m2; NetArea: 2.95 m2; GrossVolume: 17.6516 m3; NetVolume: 0.19 m3; Perimeter: 5000 mm; Width: 190 mm

# IfcSlab: Basic Roof:NLRS_27_RO_Naturoll 037_190x590x4100mm, Basic Roof:NLRS_27_RO_Naturoll 037_190x590x4100mm:13511
In: Lengte
PredefinedType: ROOF; Classification: 27 Daken (Uniformat); Material: Knauf Insulation_Ecose® glaswol_naturoll 037 190 mm
Pset_ElementShading - Roughness: 304.8 mm
Pset_ManufacturerTypeInformation - Manufacturer: Knauf Insulation B.V.
Pset_ProductRequirements - Category: Roofs
Pset_QuantityTakeOff - Reference: NLRS_27_RO_Naturoll 037_190x590x4100mm
Pset_ReinforcementBarPitchOfSlab - Description: Naturoll 037 - 190mm; Reference: NLRS_27_RO_Naturoll 037_190x590x4100mm
Pset_SlabCommon - PitchAngle: 0 deg; IsExternal: yes; Reference: NLRS_27_RO_Naturoll 037_190x590x4100mm; ThermalTransmittance: 0.184211 kg/K/s3
BaseQuantities - GrossArea: 0.092903 m2; NetArea: 2.95 m2; GrossVolume: 17.6516 m3; NetVolume: 0.19 m3; Perimeter: 5000 mm; Width: 190 mm

# IfcSlab: Basic Roof:NLRS_27_RO_Naturoll 037_220x580x3500mm, Basic Roof:NLRS_27_RO_Naturoll 037_220x580x3500mm:13531
In: Lengte
PredefinedType: ROOF; Classification: 27 Daken (Uniformat); Material: Knauf Insulation_Ecose® glaswol_naturoll 037 220 mm
Pset_ElementShading - Roughness: 304.8 mm
Pset_ManufacturerTypeInformation - Manufacturer: Knauf Insulation B.V.
Pset_ProductRequirements - Category: Roofs
Pset_QuantityTakeOff - Reference: NLRS_27_RO_Naturoll 037_220x580x3500mm
Pset_ReinforcementBarPitchOfSlab - Description: Naturoll 037 - 220mm; Reference: NLRS_27_RO_Naturoll 037_220x580x3500mm
Pset_SlabCommon - PitchAngle: 0 deg; IsExternal: yes; Reference: NLRS_27_RO_Naturoll 037_220x580x3500mm; ThermalTransmittance: 0.159091 kg/K/s3
BaseQuantities - GrossArea: 0.092903 m2; NetArea: 3.1 m2; GrossVolume: 20.4387 m3; NetVolume: 0.22 m3; Perimeter: 5000 mm; Width: 220 mm

# IfcSlab: Basic Roof:NLRS_27_RO_Naturoll 037_220x590x3500mm, Basic Roof:NLRS_27_RO_Naturoll 037_220x590x3500mm:13551
In: Lengte
PredefinedType: ROOF; Classification: 27 Daken (Uniformat); Material: Knauf Insulation_Ecose® glaswol_naturoll 037 220 mm
Pset_ElementShading - Roughness: 304.8 mm
Pset_ManufacturerTypeInformation - Manufacturer: Knauf Insulation B.V.
Pset_ProductRequirements - Category: Roofs
Pset_QuantityTakeOff - Reference: NLRS_27_RO_Naturoll 037_220x590x3500mm
Pset_ReinforcementBarPitchOfSlab - Description: Naturoll 037 - 220mm; Reference: NLRS_27_RO_Naturoll 037_220x590x3500mm
Pset_SlabCommon - PitchAngle: 0 deg; IsExternal: yes; Reference: NLRS_27_RO_Naturoll 037_220x590x3500mm; ThermalTransmittance: 0.159091 kg/K/s3
BaseQuantities - GrossArea: 0.092903 m2; NetArea: 3.1 m2; GrossVolume: 20.4387 m3; NetVolume: 0.22 m3; Perimeter: 5000 mm; Width: 220 mm

# IfcSlab: Basic Roof:NLRS_27_RO_Naturoll 037_240x590x3250mm, Basic Roof:NLRS_27_RO_Naturoll 037_240x590x3250mm:13571
In: Lengte
PredefinedType: ROOF; Classification: 27 Daken (Uniformat); Material: Knauf Insulation_Ecose® glaswol_naturoll 037 240 mm
Pset_ElementShading - Roughness: 304.8 mm
Pset_ManufacturerTypeInformation - Manufacturer: Knauf Insulation B.V.
Pset_ProductRequirements - Category: Roofs
Pset_QuantityTakeOff - Reference: NLRS_27_RO_Naturoll 037_240x590x3250mm
Pset_ReinforcementBarPitchOfSlab - Description: Naturoll 037 - 240mm; Reference: NLRS_27_RO_Naturoll 037_240x590x3250mm
Pset_SlabCommon - PitchAngle: 0 deg; IsExternal: yes; Reference: NLRS_27_RO_Naturoll 037_240x590x3250mm; ThermalTransmittance: 0.145833 kg/K/s3
BaseQuantities - GrossArea: 0.092903 m2; NetArea: 3.2 m2; GrossVolume: 22.2967 m3; NetVolume: 0.24 m3; Perimeter: 5000 mm; Width: 240 mm

# IfcSlab: Basic Roof:NLRS_27_RO_Naturoll 037_260x580x3000mm, Basic Roof:NLRS_27_RO_Naturoll 037_260x580x3000mm:13591
In: Lengte
PredefinedType: ROOF; Classification: 27 Daken (Uniformat); Material: Knauf Insulation_Ecose® glaswol_naturoll 037 260 mm
Pset_ElementShading - Roughness: 304.8 mm
Pset_ManufacturerTypeInformation - Manufacturer: Knauf Insulation B.V.
Pset_ProductRequirements - Category: Roofs
Pset_QuantityTakeOff - Reference: NLRS_27_RO_Naturoll 037_260x580x3000mm
Pset_ReinforcementBarPitchOfSlab - Description: Naturoll 037 - 260mm; Reference: NLRS_27_RO_Naturoll 037_260x580x3000mm
Pset_SlabCommon - PitchAngle: 0 deg; IsExternal: yes; Reference: NLRS_27_RO_Naturoll 037_260x580x3000mm; ThermalTransmittance: 0.134615 kg/K/s3
BaseQuantities - GrossArea: 0.092903 m2; NetArea: 3.3 m2; GrossVolume: 24.1548 m3; NetVolume: 0.26 m3; Perimeter: 5000 mm; Width: 260 mm

# IfcSlab: Basic Roof:NLRS_27_RO_Naturoll 037_265x590x3000mm, Basic Roof:NLRS_27_RO_Naturoll 037_265x590x3000mm:13729
In: Lengte
PredefinedType: ROOF; Classification: 27 Daken (Uniformat); Material: Knauf Insulation_Ecose® glaswol_naturoll 037 265 mm
Pset_ElementShading - Roughness: 304.8 mm
Pset_ManufacturerTypeInformation - Manufacturer: Knauf Insulation B.V.
Pset_ProductRequirements - Category: Roofs
Pset_QuantityTakeOff - Reference: NLRS_27_RO_Naturoll 037_265x590x3000mm
Pset_ReinforcementBarPitchOfSlab - Description: Naturoll 037 - 265mm; Reference: NLRS_27_RO_Naturoll 037_265x590x3000mm
Pset_SlabCommon - PitchAngle: 0 deg; IsExternal: yes; Reference: NLRS_27_RO_Naturoll 037_265x590x3000mm; ThermalTransmittance: 0.132075 kg/K/s3
BaseQuantities - GrossArea: 0.092903 m2; NetArea: 3.325 m2; GrossVolume: 24.6193 m3; NetVolume: 0.265 m3; Perimeter: 5000 mm; Width: 265 mm

# IfcSlab: Basic Roof:NLRS_27_RO_Naturoll 037_90x380x8200mm, Basic Roof:NLRS_27_RO_Naturoll 037_90x380x8200mm:12720
In: Lengte
PredefinedType: ROOF; Classification: 27 Daken (Uniformat); Material: Knauf Insulation_Ecose® glaswol_naturoll 037 90 mm
Pset_ElementShading - Roughness: 304.8 mm
Pset_ManufacturerTypeInformation - Manufacturer: Knauf Insulation B.V.
Pset_ProductRequirements - Category: Roofs
Pset_QuantityTakeOff - Reference: NLRS_27_RO_Naturoll 037_90x380x8200mm
Pset_ReinforcementBarPitchOfSlab - Description: Naturoll 037 - 90mm; Reference: NLRS_27_RO_Naturoll 037_90x380x8200mm
Pset_SlabCommon - PitchAngle: 0 deg; IsExternal: yes; Reference: NLRS_27_RO_Naturoll 037_90x380x8200mm; ThermalTransmittance: 0.388889 kg/K/s3
BaseQuantities - GrossArea: 0.092903 m2; NetArea: 2.45 m2; GrossVolume: 8.36127 m3; NetVolume: 0.09 m3; Perimeter: 5000 mm; Width: 90 mm

# IfcSlab: Basic Roof:NLRS_27_RO_Naturoll 037_90x580x8200mm, Basic Roof:NLRS_27_RO_Naturoll 037_90x580x8200mm:12989
In: Lengte
PredefinedType: ROOF; Classification: 27 Daken (Uniformat); Material: Knauf Insulation_Ecose® glaswol_naturoll 037 90 mm
Pset_ElementShading - Roughness: 304.8 mm
Pset_ManufacturerTypeInformation - Manufacturer: Knauf Insulation B.V.
Pset_ProductRequirements - Category: Roofs
Pset_QuantityTakeOff - Reference: NLRS_27_RO_Naturoll 037_90x580x8200mm
Pset_ReinforcementBarPitchOfSlab - Description: Naturoll 037 - 90mm; Reference: NLRS_27_RO_Naturoll 037_90x580x8200mm
Pset_SlabCommon - PitchAngle: 0 deg; IsExternal: yes; Reference: NLRS_27_RO_Naturoll 037_90x580x8200mm; ThermalTransmittance: 0.388889 kg/K/s3
BaseQuantities - GrossArea: 0.092903 m2; NetArea: 2.45 m2; GrossVolume: 8.36127 m3; NetVolume: 0.09 m3; Perimeter: 5000 mm; Width: 90 mm

# IfcSlab: Floor:NLRS_23_FL_Naturoll 037_120x380x6500mm, Floor:NLRS_23_FL_Naturoll 037_120x380x6500mm:13029
In: Begane grond
Type - PredefinedType: FLOOR; Material: Knauf Insulation_Ecose® glaswol_naturoll 037 120 mm
Type - Analytical Properties - Roughness: 1; Thermal mass: 0; Absorptance: 0.1; Heat Transfer Coefficient (U): 0.291667; Thermal Resistance (R): 3.42857
Type - Construction - Function: Interior; Default Thickness: 120 mm
Type - Graphics - Coarse Scale Fill Color: 0
Type - Identity Data - Type Image: Raster image: Naturoll 037.jpg (3); Assembly Code: 23; Assembly Description: Vloeren; Description: Naturoll 037 - 120mm; Manufacturer: Knauf Insulation B.V.; Model: Naturoll 037 is een onbeklede glaswoldeken met ECOSE® Technology; Type Name: NLRS_23_FL_Naturoll 037_120x380x6500mm; URL: www.knaufinsulation.nl
Type - Other - Category: Floors; Family Name: Floor
Type - Pset_ElementShading - Roughness: 304.8 mm
Type - Pset_ManufacturerTypeInformation - Manufacturer: Knauf Insulation B.V.
Type - Pset_ProductRequirements - Category: Floors
Type - Pset_QuantityTakeOff - Reference: NLRS_23_FL_Naturoll 037_120x380x6500mm
Type - Pset_ReinforcementBarPitchOfSlab - Description: Naturoll 037 - 120mm; Reference: NLRS_23_FL_Naturoll 037_120x380x6500mm
Type - Pset_SlabCommon - IsExternal: no; Reference: NLRS_23_FL_Naturoll 037_120x380x6500mm; ThermalTransmittance: 0.291667 kg/K/s3
Classification: 23 Vloeren (Uniformat)
Pset_SlabCommon - LoadBearing: no; PitchAngle: 0 deg
BaseQuantities - GrossArea: 1 m2; NetArea: 2.6 m2; GrossVolume: 120 m3; NetVolume: 0.12 m3; Perimeter: 5000 mm; Width: 120 mm
Constraints - Height Offset From Level: 0 mm; Level: Level: Begane grond; Related to Mass: no; Room Bounding: yes
Dimensions - Elevation at Top: 0 mm; Area: 1 m2; Elevation at Bottom: -120 mm; Perimeter: 5000 mm; Thickness: 120 mm; Volume: 0.12 m3
Other - Family: Floor: NLRS_23_FL_Naturoll 037_120x380x6500mm; Family and Type: Floor: NLRS_23_FL_Naturoll 037_120x380x6500mm; Type: Floor: NLRS_23_FL_Naturoll 037_120x380x6500mm; Type Id: Floor: NLRS_23_FL_Naturoll 037_120x380x6500mm
Phasing - Phase Created: New Construction
Structural - Enable Analytical Model: no; Structural: no

# IfcSlab: Floor:NLRS_23_FL_Naturoll 037_120x580x6500mm, Floor:NLRS_23_FL_Naturoll 037_120x580x6500mm:13054
In: Begane grond
Type - PredefinedType: FLOOR; Material: Knauf Insulation_Ecose® glaswol_naturoll 037 120 mm
Type - Analytical Properties - Roughness: 1; Thermal mass: 0; Absorptance: 0.1; Heat Transfer Coefficient (U): 0.291667; Thermal Resistance (R): 3.42857
Type - Construction - Function: Interior; Default Thickness: 120 mm
Type - Graphics - Coarse Scale Fill Color: 0
Type - Identity Data - Type Image: Raster image: Naturoll 037.jpg (3); Assembly Code: 23; Assembly Description: Vloeren; Description: Naturoll 037 - 120mm; Manufacturer: Knauf Insulation B.V.; Model: Naturoll 037 is een onbeklede glaswoldeken met ECOSE® Technology; Type Name: NLRS_23_FL_Naturoll 037_120x580x6500mm; URL: www.knaufinsulation.nl
Type - Other - Category: Floors; Family Name: Floor
Type - Pset_ElementShading - Roughness: 304.8 mm
Type - Pset_ManufacturerTypeInformation - Manufacturer: Knauf Insulation B.V.
Type - Pset_ProductRequirements - Category: Floors
Type - Pset_QuantityTakeOff - Reference: NLRS_23_FL_Naturoll 037_120x580x6500mm
Type - Pset_ReinforcementBarPitchOfSlab - Description: Naturoll 037 - 120mm; Reference: NLRS_23_FL_Naturoll 037_120x580x6500mm
Type - Pset_SlabCommon - IsExternal: no; Reference: NLRS_23_FL_Naturoll 037_120x580x6500mm; ThermalTransmittance: 0.291667 kg/K/s3
Classification: 23 Vloeren (Uniformat)
Pset_SlabCommon - LoadBearing: no; PitchAngle: 0 deg
BaseQuantities - GrossArea: 1 m2; NetArea: 2.6 m2; GrossVolume: 120 m3; NetVolume: 0.12 m3; Perimeter: 5000 mm; Width: 120 mm
Constraints - Height Offset From Level: 0 mm; Level: Level: Begane grond; Related to Mass: no; Room Bounding: yes
Dimensions - Elevation at Top: 0 mm; Area: 1 m2; Elevation at Bottom: -120 mm; Perimeter: 5000 mm; Thickness: 120 mm; Volume: 0.12 m3
Other - Family: Floor: NLRS_23_FL_Naturoll 037_120x580x6500mm; Family and Type: Floor: NLRS_23_FL_Naturoll 037_120x580x6500mm; Type: Floor: NLRS_23_FL_Naturoll 037_120x580x6500mm; Type Id: Floor: NLRS_23_FL_Naturoll 037_120x580x6500mm
Phasing - Phase Created: New Construction
Structural - Enable Analytical Model: no; Structural: no

# IfcSlab: Floor:NLRS_23_FL_Naturoll 037_140x380x5600mm, Floor:NLRS_23_FL_Naturoll 037_140x380x5600mm:13079
In: Begane grond
Type - PredefinedType: FLOOR; Material: Knauf Insulation_Ecose® glaswol_naturoll 037 140 mm
Type - Analytical Properties - Roughness: 1; Thermal mass: 0; Absorptance: 0.1; Heat Transfer Coefficient (U): 0.25; Thermal Resistance (R): 4
Type - Construction - Function: Interior; Default Thickness: 140 mm
Type - Graphics - Coarse Scale Fill Color: 0
Type - Identity Data - Type Image: Raster image: Naturoll 037.jpg (3); Assembly Code: 23; Assembly Description: Vloeren; Description: Naturoll 037 - 140mm; Manufacturer: Knauf Insulation B.V.; Model: Naturoll 037 is een onbeklede glaswoldeken met ECOSE® Technology; Type Name: NLRS_23_FL_Naturoll 037_140x380x5600mm; URL: www.knaufinsulation.nl
Type - Other - Category: Floors; Family Name: Floor
Type - Pset_ElementShading - Roughness: 304.8 mm
Type - Pset_ManufacturerTypeInformation - Manufacturer: Knauf Insulation B.V.
Type - Pset_ProductRequirements - Category: Floors
Type - Pset_QuantityTakeOff - Reference: NLRS_23_FL_Naturoll 037_140x380x5600mm
Type - Pset_ReinforcementBarPitchOfSlab - Description: Naturoll 037 - 140mm; Reference: NLRS_23_FL_Naturoll 037_140x380x5600mm
Type - Pset_SlabCommon - IsExternal: no; Reference: NLRS_23_FL_Naturoll 037_140x380x5600mm; ThermalTransmittance: 0.25 kg/K/s3
Classification: 23 Vloeren (Uniformat)
Pset_SlabCommon - LoadBearing: no; PitchAngle: 0 deg
BaseQuantities - GrossArea: 1 m2; NetArea: 2.7 m2; GrossVolume: 140 m3; NetVolume: 0.14 m3; Perimeter: 5000 mm; Width: 140 mm
Constraints - Height Offset From Level: 0 mm; Related to Mass: no; Room Bounding: yes; Level: Level: Begane grond
Dimensions - Elevation at Top: 0 mm; Area: 1 m2; Elevation at Bottom: -140 mm; Perimeter: 5000 mm; Thickness: 140 mm; Volume: 0.14 m3
Other - Family: Floor: NLRS_23_FL_Naturoll 037_140x380x5600mm; Family and Type: Floor: NLRS_23_FL_Naturoll 037_140x380x5600mm; Type: Floor: NLRS_23_FL_Naturoll 037_140x380x5600mm; Type Id: Floor: NLRS_23_FL_Naturoll 037_140x380x5600mm
Phasing - Phase Created: New Construction
Structural - Enable Analytical Model: no; Structural: no

# IfcSlab: Floor:NLRS_23_FL_Naturoll 037_140x580x5600mm, Floor:NLRS_23_FL_Naturoll 037_140x580x5600mm:13312
In: Begane grond
Type - PredefinedType: FLOOR; Material: Knauf Insulation_Ecose® glaswol_naturoll 037 140 mm
Type - Analytical Properties - Roughness: 1; Thermal mass: 0; Thermal Resistance (R): 4; Absorptance: 0.1; Heat Transfer Coefficient (U): 0.25
Type - Construction - Function: Interior; Default Thickness: 140 mm
Type - Graphics - Coarse Scale Fill Color: 0
Type - Identity Data - Type Image: Raster image: Naturoll 037.jpg (3); Assembly Code: 23; Assembly Description: Vloeren; Description: Naturoll 037 - 140mm; Manufacturer: Knauf Insulation B.V.; Model: Naturoll 037 is een onbeklede glaswoldeken met ECOSE® Technology; Type Name: NLRS_23_FL_Naturoll 037_140x580x5600mm; URL: www.knaufinsulation.nl
Type - Other - Category: Floors; Family Name: Floor
Type - Pset_ElementShading - Roughness: 304.8 mm
Type - Pset_ManufacturerTypeInformation - Manufacturer: Knauf Insulation B.V.
Type - Pset_ProductRequirements - Category: Floors
Type - Pset_QuantityTakeOff - Reference: NLRS_23_FL_Naturoll 037_140x580x5600mm
Type - Pset_ReinforcementBarPitchOfSlab - Description: Naturoll 037 - 140mm; Reference: NLRS_23_FL_Naturoll 037_140x580x5600mm
Type - Pset_SlabCommon - IsExternal: no; ThermalTransmittance: 0.25 kg/K/s3; Reference: NLRS_23_FL_Naturoll 037_140x580x5600mm
Classification: 23 Vloeren (Uniformat)
Pset_SlabCommon - LoadBearing: no; PitchAngle: 0 deg
BaseQuantities - GrossArea: 1 m2; NetArea: 2.7 m2; GrossVolume: 140 m3; NetVolume: 0.14 m3; Perimeter: 5000 mm; Width: 140 mm
Constraints - Height Offset From Level: 0 mm; Related to Mass: no; Room Bounding: yes; Level: Level: Begane grond
Dimensions - Elevation at Top: 0 mm; Area: 1 m2; Elevation at Bottom: -140 mm; Perimeter: 5000 mm; Thickness: 140 mm; Volume: 0.14 m3
Other - Family: Floor: NLRS_23_FL_Naturoll 037_140x580x5600mm; Family and Type: Floor: NLRS_23_FL_Naturoll 037_140x580x5600mm; Type: Floor: NLRS_23_FL_Naturoll 037_140x580x5600mm; Type Id: Floor: NLRS_23_FL_Naturoll 037_140x580x5600mm
Phasing - Phase Created: New Construction
Structural - Enable Analytical Model: no; Structural: no

# IfcSlab: Floor:NLRS_23_FL_Naturoll 037_170x380x5600mm, Floor:NLRS_23_FL_Naturoll 037_170x380x5600mm:13334
In: Begane grond
Type - PredefinedType: FLOOR; Material: Knauf Insulation_Ecose® glaswol_naturoll 037 170 mm
Type - Analytical Properties - Roughness: 1; Thermal mass: 0; Absorptance: 0.1; Heat Transfer Coefficient (U): 0.205882; Thermal Resistance (R): 4.85714
Type - Construction - Function: Interior; Default Thickness: 170 mm
Type - Graphics - Coarse Scale Fill Color: 0
Type - Identity Data - Type Image: Raster image: Naturoll 037.jpg (3); Assembly Code: 23; Assembly Description: Vloeren; Description: Naturoll 037 - 170mm; Manufacturer: Knauf Insulation B.V.; Model: Naturoll 037 is een onbeklede glaswoldeken met ECOSE® Technology; Type Name: NLRS_23_FL_Naturoll 037_170x380x5600mm; URL: www.knaufinsulation.nl
Type - Other - Category: Floors; Family Name: Floor
Type - Pset_ElementShading - Roughness: 304.8 mm
Type - Pset_ManufacturerTypeInformation - Manufacturer: Knauf Insulation B.V.
Type - Pset_ProductRequirements - Category: Floors
Type - Pset_QuantityTakeOff - Reference: NLRS_23_FL_Naturoll 037_170x380x5600mm
Type - Pset_ReinforcementBarPitchOfSlab - Description: Naturoll 037 - 170mm; Reference: NLRS_23_FL_Naturoll 037_170x380x5600mm
Type - Pset_SlabCommon - IsExternal: no; Reference: NLRS_23_FL_Naturoll 037_170x380x5600mm; ThermalTransmittance: 0.205882 kg/K/s3
Classification: 23 Vloeren (Uniformat)
Pset_SlabCommon - LoadBearing: no; PitchAngle: 0 deg
BaseQuantities - GrossArea: 1 m2; NetArea: 2.85 m2; GrossVolume: 170 m3; NetVolume: 0.17 m3; Perimeter: 5000 mm; Width: 170 mm
Constraints - Height Offset From Level: 0 mm; Related to Mass: no; Room Bounding: yes; Level: Level: Begane grond
Dimensions - Elevation at Top: 0 mm; Area: 1 m2; Elevation at Bottom: -170 mm; Perimeter: 5000 mm; Thickness: 170 mm; Volume: 0.17 m3
Other - Family: Floor: NLRS_23_FL_Naturoll 037_170x380x5600mm; Family and Type: Floor: NLRS_23_FL_Naturoll 037_170x380x5600mm; Type: Floor: NLRS_23_FL_Naturoll 037_170x380x5600mm; Type Id: Floor: NLRS_23_FL_Naturoll 037_170x380x5600mm
Phasing - Phase Created: New Construction
Structural - Enable Analytical Model: no; Structural: no

# IfcSlab: Floor:NLRS_23_FL_Naturoll 037_170x580x5600mm, Floor:NLRS_23_FL_Naturoll 037_170x580x5600mm:13356
In: Begane grond
Type - PredefinedType: FLOOR; Material: Knauf Insulation_Ecose® glaswol_naturoll 037 170 mm
Type - Analytical Properties - Roughness: 1; Thermal mass: 0; Absorptance: 0.1; Heat Transfer Coefficient (U): 0.205882; Thermal Resistance (R): 4.85714
Type - Construction - Function: Interior; Default Thickness: 170 mm
Type - Graphics - Coarse Scale Fill Color: 0
Type - Identity Data - Type Image: Raster image: Naturoll 037.jpg (3); Assembly Code: 23; Assembly Description: Vloeren; Description: Naturoll 037 - 170mm; Manufacturer: Knauf Insulation B.V.; Model: Naturoll 037 is een onbeklede glaswoldeken met ECOSE® Technology; Type Name: NLRS_23_FL_Naturoll 037_170x580x5600mm; URL: www.knaufinsulation.nl
Type - Other - Category: Floors; Family Name: Floor
Type - Pset_ElementShading - Roughness: 304.8 mm
Type - Pset_ManufacturerTypeInformation - Manufacturer: Knauf Insulation B.V.
Type - Pset_ProductRequirements - Category: Floors
Type - Pset_QuantityTakeOff - Reference: NLRS_23_FL_Naturoll 037_170x580x5600mm
Type - Pset_ReinforcementBarPitchOfSlab - Description: Naturoll 037 - 170mm; Reference: NLRS_23_FL_Naturoll 037_170x580x5600mm
Type - Pset_SlabCommon - IsExternal: no; Reference: NLRS_23_FL_Naturoll 037_170x580x5600mm; ThermalTransmittance: 0.205882 kg/K/s3
Classification: 23 Vloeren (Uniformat)
Pset_SlabCommon - LoadBearing: no; PitchAngle: 0 deg
BaseQuantities - GrossArea: 1 m2; NetArea: 2.85 m2; GrossVolume: 170 m3; NetVolume: 0.17 m3; Perimeter: 5000 mm; Width: 170 mm
Constraints - Height Offset From Level: 0 mm; Level: Level: Begane grond; Related to Mass: no; Room Bounding: yes
Dimensions - Elevation at Top: 0 mm; Area: 1 m2; Elevation at Bottom: -170 mm; Perimeter: 5000 mm; Thickness: 170 mm; Volume: 0.17 m3
Other - Family: Floor: NLRS_23_FL_Naturoll 037_170x580x5600mm; Family and Type: Floor: NLRS_23_FL_Naturoll 037_170x580x5600mm; Type: Floor: NLRS_23_FL_Naturoll 037_170x580x5600mm; Type Id: Floor: NLRS_23_FL_Naturoll 037_170x580x5600mm
Phasing - Phase Created: New Construction
Structural - Enable Analytical Model: no; Structural: no

# IfcSlab: Floor:NLRS_23_FL_Naturoll 037_170x590x5600mm, Floor:NLRS_23_FL_Naturoll 037_170x590x5600mm:13378
In: Begane grond
Type - PredefinedType: FLOOR; Material: Knauf Insulation_Ecose® glaswol_naturoll 037 170 mm
Type - Analytical Properties - Roughness: 1; Thermal mass: 0; Absorptance: 0.1; Heat Transfer Coefficient (U): 0.205882; Thermal Resistance (R): 4.85714
Type - Construction - Function: Interior; Default Thickness: 170 mm
Type - Graphics - Coarse Scale Fill Color: 0
Type - Identity Data - Type Image: Raster image: Naturoll 037.jpg (3); Assembly Code: 23; Assembly Description: Vloeren; Description: Naturoll 037 - 170mm; Manufacturer: Knauf Insulation B.V.; Model: Naturoll 037 is een onbeklede glaswoldeken met ECOSE® Technology; Type Name: NLRS_23_FL_Naturoll 037_170x590x5600mm; URL: www.knaufinsulation.nl
Type - Other - Category: Floors; Family Name: Floor
Type - Pset_ElementShading - Roughness: 304.8 mm
Type - Pset_ManufacturerTypeInformation - Manufacturer: Knauf Insulation B.V.
Type - Pset_ProductRequirements - Category: Floors
Type - Pset_QuantityTakeOff - Reference: NLRS_23_FL_Naturoll 037_170x590x5600mm
Type - Pset_ReinforcementBarPitchOfSlab - Description: Naturoll 037 - 170mm; Reference: NLRS_23_FL_Naturoll 037_170x590x5600mm
Type - Pset_SlabCommon - IsExternal: no; Reference: NLRS_23_FL_Naturoll 037_170x590x5600mm; ThermalTransmittance: 0.205882 kg/K/s3
Classification: 23 Vloeren (Uniformat)
Pset_SlabCommon - LoadBearing: no; PitchAngle: 0 deg
BaseQuantities - GrossArea: 1 m2; NetArea: 2.85 m2; GrossVolume: 170 m3; NetVolume: 0.17 m3; Perimeter: 5000 mm; Width: 170 mm
Constraints - Height Offset From Level: 0 mm; Related to Mass: no; Room Bounding: yes; Level: Level: Begane grond
Dimensions - Elevation at Top: 0 mm; Area: 1 m2; Elevation at Bottom: -170 mm; Perimeter: 5000 mm; Thickness: 170 mm; Volume: 0.17 m3
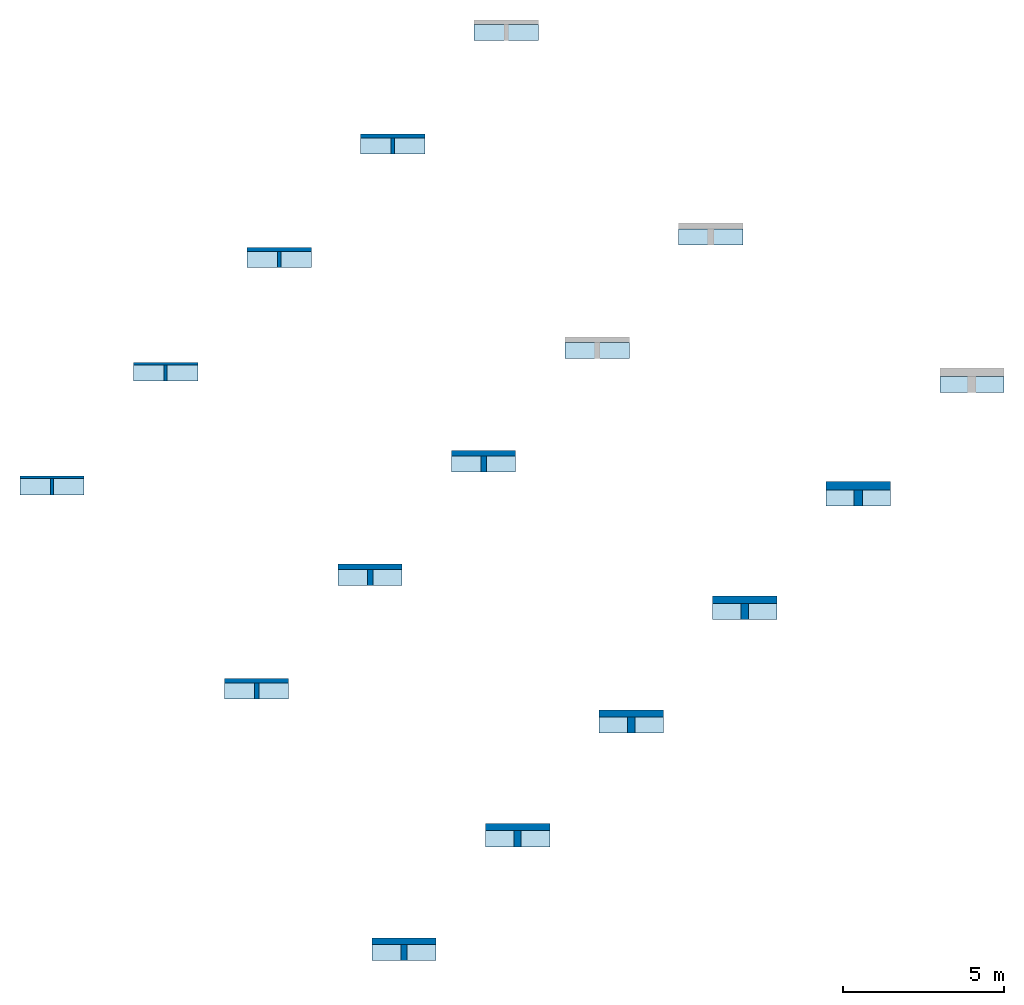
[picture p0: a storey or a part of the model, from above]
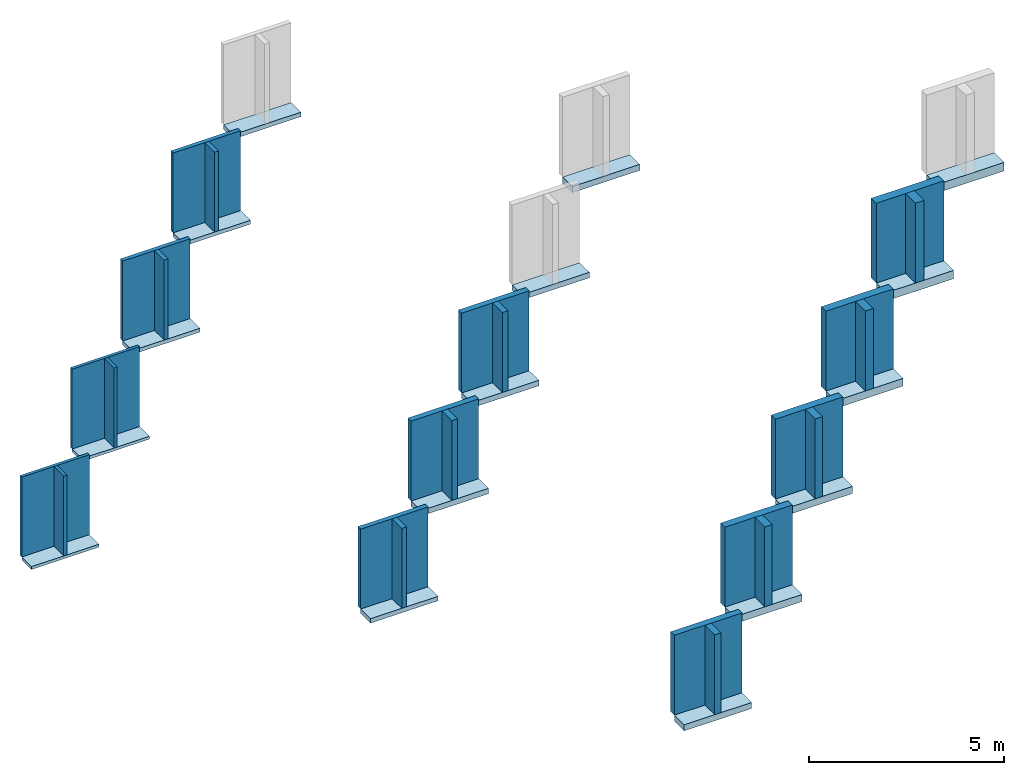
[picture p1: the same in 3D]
Properties of the parts of a building model (IFC2X3), part 2 of 3

# IfcSlab: Floor:NLRS_23_FL_Naturoll 037_170x590x5600mm, Floor:NLRS_23_FL_Naturoll 037_170x590x5600mm:13378
Other - Family: Floor: NLRS_23_FL_Naturoll 037_170x590x5600mm; Family and Type: Floor: NLRS_23_FL_Naturoll 037_170x590x5600mm; Type: Floor: NLRS_23_FL_Naturoll 037_170x590x5600mm; Type Id: Floor: NLRS_23_FL_Naturoll 037_170x590x5600mm
Phasing - Phase Created: New Construction
Structural - Enable Analytical Model: no; Structural: no

# IfcSlab: Floor:NLRS_23_FL_Naturoll 037_190x580x4100mm, Floor:NLRS_23_FL_Naturoll 037_190x580x4100mm:13400
In: Begane grond
Type - PredefinedType: FLOOR; Material: Knauf Insulation_Ecose® glaswol_naturoll 037 190 mm
Type - Analytical Properties - Roughness: 1; Thermal mass: 0; Absorptance: 0.1; Heat Transfer Coefficient (U): 0.184211; Thermal Resistance (R): 5.42857
Type - Construction - Function: Interior; Default Thickness: 190 mm
Type - Graphics - Coarse Scale Fill Color: 0
Type - Identity Data - Type Image: Raster image: Naturoll 037.jpg (3); Assembly Code: 23; Assembly Description: Vloeren; Description: Naturoll 037 - 190mm; Manufacturer: Knauf Insulation B.V.; Model: Naturoll 037 is een onbeklede glaswoldeken met ECOSE® Technology; Type Name: NLRS_23_FL_Naturoll 037_190x580x4100mm; URL: www.knaufinsulation.nl
Type - Other - Category: Floors; Family Name: Floor
Type - Pset_ElementShading - Roughness: 304.8 mm
Type - Pset_ManufacturerTypeInformation - Manufacturer: Knauf Insulation B.V.
Type - Pset_ProductRequirements - Category: Floors
Type - Pset_QuantityTakeOff - Reference: NLRS_23_FL_Naturoll 037_190x580x4100mm
Type - Pset_ReinforcementBarPitchOfSlab - Description: Naturoll 037 - 190mm; Reference: NLRS_23_FL_Naturoll 037_190x580x4100mm
Type - Pset_SlabCommon - IsExternal: no; Reference: NLRS_23_FL_Naturoll 037_190x580x4100mm; ThermalTransmittance: 0.184211 kg/K/s3
Classification: 23 Vloeren (Uniformat)
Pset_SlabCommon - LoadBearing: no; PitchAngle: 0 deg
BaseQuantities - GrossArea: 1 m2; NetArea: 2.95 m2; GrossVolume: 190 m3; NetVolume: 0.19 m3; Perimeter: 5000 mm; Width: 190 mm
Constraints - Height Offset From Level: 0 mm; Related to Mass: no; Room Bounding: yes; Level: Level: Begane grond
Dimensions - Elevation at Top: 0 mm; Area: 1 m2; Elevation at Bottom: -190 mm; Perimeter: 5000 mm; Thickness: 190 mm; Volume: 0.19 m3
Other - Family: Floor: NLRS_23_FL_Naturoll 037_190x580x4100mm; Family and Type: Floor: NLRS_23_FL_Naturoll 037_190x580x4100mm; Type: Floor: NLRS_23_FL_Naturoll 037_190x580x4100mm; Type Id: Floor: NLRS_23_FL_Naturoll 037_190x580x4100mm
Phasing - Phase Created: New Construction
Structural - Enable Analytical Model: no; Structural: no

# IfcSlab: Floor:NLRS_23_FL_Naturoll 037_190x590x4100mm, Floor:NLRS_23_FL_Naturoll 037_190x590x4100mm:13499
In: Begane grond
Type - PredefinedType: FLOOR; Material: Knauf Insulation_Ecose® glaswol_naturoll 037 190 mm
Type - Analytical Properties - Roughness: 1; Thermal mass: 0; Absorptance: 0.1; Heat Transfer Coefficient (U): 0.184211; Thermal Resistance (R): 5.42857
Type - Construction - Function: Interior; Default Thickness: 190 mm
Type - Graphics - Coarse Scale Fill Color: 0
Type - Identity Data - Type Image: Raster image: Naturoll 037.jpg (3); Assembly Code: 23; Assembly Description: Vloeren; Description: Naturoll 037 - 190mm; Manufacturer: Knauf Insulation B.V.; Model: Naturoll 037 is een onbeklede glaswoldeken met ECOSE® Technology; Type Name: NLRS_23_FL_Naturoll 037_190x590x4100mm; URL: www.knaufinsulation.nl
Type - Other - Category: Floors; Family Name: Floor
Type - Pset_ElementShading - Roughness: 304.8 mm
Type - Pset_ManufacturerTypeInformation - Manufacturer: Knauf Insulation B.V.
Type - Pset_ProductRequirements - Category: Floors
Type - Pset_QuantityTakeOff - Reference: NLRS_23_FL_Naturoll 037_190x590x4100mm
Type - Pset_ReinforcementBarPitchOfSlab - Description: Naturoll 037 - 190mm; Reference: NLRS_23_FL_Naturoll 037_190x590x4100mm
Type - Pset_SlabCommon - IsExternal: no; Reference: NLRS_23_FL_Naturoll 037_190x590x4100mm; ThermalTransmittance: 0.184211 kg/K/s3
Classification: 23 Vloeren (Uniformat)
Pset_SlabCommon - LoadBearing: no; PitchAngle: 0 deg
BaseQuantities - GrossArea: 1 m2; NetArea: 2.95 m2; GrossVolume: 190 m3; NetVolume: 0.19 m3; Perimeter: 5000 mm; Width: 190 mm
Constraints - Height Offset From Level: 0 mm; Related to Mass: no; Room Bounding: yes; Level: Level: Begane grond
Dimensions - Elevation at Top: 0 mm; Area: 1 m2; Elevation at Bottom: -190 mm; Perimeter: 5000 mm; Thickness: 190 mm; Volume: 0.19 m3
Other - Family: Floor: NLRS_23_FL_Naturoll 037_190x590x4100mm; Family and Type: Floor: NLRS_23_FL_Naturoll 037_190x590x4100mm; Type: Floor: NLRS_23_FL_Naturoll 037_190x590x4100mm; Type Id: Floor: NLRS_23_FL_Naturoll 037_190x590x4100mm
Phasing - Phase Created: New Construction
Structural - Enable Analytical Model: no; Structural: no

# IfcSlab: Floor:NLRS_23_FL_Naturoll 037_220x580x3500mm, Floor:NLRS_23_FL_Naturoll 037_220x580x3500mm:13519
In: Begane grond
Type - PredefinedType: FLOOR; Material: Knauf Insulation_Ecose® glaswol_naturoll 037 220 mm
Type - Analytical Properties - Roughness: 1; Thermal mass: 0; Absorptance: 0.1; Heat Transfer Coefficient (U): 0.159091; Thermal Resistance (R): 6.28571
Type - Construction - Function: Interior; Default Thickness: 220 mm
Type - Graphics - Coarse Scale Fill Color: 0
Type - Identity Data - Type Image: Raster image: Naturoll 037.jpg (3); Assembly Code: 23; Assembly Description: Vloeren; Description: Naturoll 037 - 220mm; Manufacturer: Knauf Insulation B.V.; Model: Naturoll 037 is een onbeklede glaswoldeken met ECOSE® Technology; Type Name: NLRS_23_FL_Naturoll 037_220x580x3500mm; URL: www.knaufinsulation.nl
Type - Other - Category: Floors; Family Name: Floor
Type - Pset_ElementShading - Roughness: 304.8 mm
Type - Pset_ManufacturerTypeInformation - Manufacturer: Knauf Insulation B.V.
Type - Pset_ProductRequirements - Category: Floors
Type - Pset_QuantityTakeOff - Reference: NLRS_23_FL_Naturoll 037_220x580x3500mm
Type - Pset_ReinforcementBarPitchOfSlab - Description: Naturoll 037 - 220mm; Reference: NLRS_23_FL_Naturoll 037_220x580x3500mm
Type - Pset_SlabCommon - IsExternal: no; Reference: NLRS_23_FL_Naturoll 037_220x580x3500mm; ThermalTransmittance: 0.159091 kg/K/s3
Classification: 23 Vloeren (Uniformat)
Pset_SlabCommon - LoadBearing: no; PitchAngle: 0 deg
BaseQuantities - GrossArea: 1 m2; NetArea: 3.1 m2; GrossVolume: 220 m3; NetVolume: 0.22 m3; Perimeter: 5000 mm; Width: 220 mm
Constraints - Height Offset From Level: 0 mm; Related to Mass: no; Room Bounding: yes; Level: Level: Begane grond
Dimensions - Elevation at Top: 0 mm; Area: 1 m2; Elevation at Bottom: -220 mm; Perimeter: 5000 mm; Thickness: 220 mm; Volume: 0.22 m3
Other - Family: Floor: NLRS_23_FL_Naturoll 037_220x580x3500mm; Family and Type: Floor: NLRS_23_FL_Naturoll 037_220x580x3500mm; Type: Floor: NLRS_23_FL_Naturoll 037_220x580x3500mm; Type Id: Floor: NLRS_23_FL_Naturoll 037_220x580x3500mm
Phasing - Phase Created: New Construction
Structural - Enable Analytical Model: no; Structural: no

# IfcSlab: Floor:NLRS_23_FL_Naturoll 037_220x590x3500mm, Floor:NLRS_23_FL_Naturoll 037_220x590x3500mm:13539
In: Begane grond
Type - PredefinedType: FLOOR; Material: Knauf Insulation_Ecose® glaswol_naturoll 037 220 mm
Type - Analytical Properties - Roughness: 1; Thermal mass: 0; Absorptance: 0.1; Heat Transfer Coefficient (U): 0.159091; Thermal Resistance (R): 6.28571
Type - Construction - Function: Interior; Default Thickness: 220 mm
Type - Graphics - Coarse Scale Fill Color: 0
Type - Identity Data - Type Image: Raster image: Naturoll 037.jpg (3); Assembly Code: 23; Assembly Description: Vloeren; Description: Naturoll 037 - 220mm; Manufacturer: Knauf Insulation B.V.; Model: Naturoll 037 is een onbeklede glaswoldeken met ECOSE® Technology; Type Name: NLRS_23_FL_Naturoll 037_220x590x3500mm; URL: www.knaufinsulation.nl
Type - Other - Category: Floors; Family Name: Floor
Type - Pset_ElementShading - Roughness: 304.8 mm
Type - Pset_ManufacturerTypeInformation - Manufacturer: Knauf Insulation B.V.
Type - Pset_ProductRequirements - Category: Floors
Type - Pset_QuantityTakeOff - Reference: NLRS_23_FL_Naturoll 037_220x590x3500mm
Type - Pset_ReinforcementBarPitchOfSlab - Description: Naturoll 037 - 220mm; Reference: NLRS_23_FL_Naturoll 037_220x590x3500mm
Type - Pset_SlabCommon - IsExternal: no; Reference: NLRS_23_FL_Naturoll 037_220x590x3500mm; ThermalTransmittance: 0.159091 kg/K/s3
Classification: 23 Vloeren (Uniformat)
Pset_SlabCommon - LoadBearing: no; PitchAngle: 0 deg
BaseQuantities - GrossArea: 1 m2; NetArea: 3.1 m2; GrossVolume: 220 m3; NetVolume: 0.22 m3; Perimeter: 5000 mm; Width: 220 mm
Constraints - Height Offset From Level: 0 mm; Related to Mass: no; Room Bounding: yes; Level: Level: Begane grond
Dimensions - Elevation at Top: 0 mm; Area: 1 m2; Elevation at Bottom: -220 mm; Perimeter: 5000 mm; Thickness: 220 mm; Volume: 0.22 m3
Other - Family: Floor: NLRS_23_FL_Naturoll 037_220x590x3500mm; Family and Type: Floor: NLRS_23_FL_Naturoll 037_220x590x3500mm; Type: Floor: NLRS_23_FL_Naturoll 037_220x590x3500mm; Type Id: Floor: NLRS_23_FL_Naturoll 037_220x590x3500mm
Phasing - Phase Created: New Construction
Structural - Enable Analytical Model: no; Structural: no

# IfcSlab: Floor:NLRS_23_FL_Naturoll 037_240x590x3250mm, Floor:NLRS_23_FL_Naturoll 037_240x590x3250mm:13559
In: Begane grond
Type - PredefinedType: FLOOR; Material: Knauf Insulation_Ecose® glaswol_naturoll 037 240 mm
Type - Analytical Properties - Roughness: 1; Thermal mass: 0; Absorptance: 0.1; Heat Transfer Coefficient (U): 0.145833; Thermal Resistance (R): 6.85714
Type - Construction - Function: Interior; Default Thickness: 240 mm
Type - Graphics - Coarse Scale Fill Color: 0
Type - Identity Data - Type Image: Raster image: Naturoll 037.jpg (3); Assembly Code: 23; Assembly Description: Vloeren; Description: Naturoll 037 - 240mm; Manufacturer: Knauf Insulation B.V.; Model: Naturoll 037 is een onbeklede glaswoldeken met ECOSE® Technology; Type Name: NLRS_23_FL_Naturoll 037_240x590x3250mm; URL: www.knaufinsulation.nl
Type - Other - Category: Floors; Family Name: Floor
Type - Pset_ElementShading - Roughness: 304.8 mm
Type - Pset_ManufacturerTypeInformation - Manufacturer: Knauf Insulation B.V.
Type - Pset_ProductRequirements - Category: Floors
Type - Pset_QuantityTakeOff - Reference: NLRS_23_FL_Naturoll 037_240x590x3250mm
Type - Pset_ReinforcementBarPitchOfSlab - Description: Naturoll 037 - 240mm; Reference: NLRS_23_FL_Naturoll 037_240x590x3250mm
Type - Pset_SlabCommon - IsExternal: no; Reference: NLRS_23_FL_Naturoll 037_240x590x3250mm; ThermalTransmittance: 0.145833 kg/K/s3
Classification: 23 Vloeren (Uniformat)
Pset_SlabCommon - LoadBearing: no; PitchAngle: 0 deg
BaseQuantities - GrossArea: 1 m2; NetArea: 3.2 m2; GrossVolume: 240 m3; NetVolume: 0.24 m3; Perimeter: 5000 mm; Width: 240 mm
Constraints - Height Offset From Level: 0 mm; Related to Mass: no; Room Bounding: yes; Level: Level: Begane grond
Dimensions - Elevation at Top: 0 mm; Area: 1 m2; Elevation at Bottom: -240 mm; Perimeter: 5000 mm; Thickness: 240 mm; Volume: 0.24 m3
Other - Family: Floor: NLRS_23_FL_Naturoll 037_240x590x3250mm; Family and Type: Floor: NLRS_23_FL_Naturoll 037_240x590x3250mm; Type: Floor: NLRS_23_FL_Naturoll 037_240x590x3250mm; Type Id: Floor: NLRS_23_FL_Naturoll 037_240x590x3250mm
Phasing - Phase Created: New Construction
Structural - Enable Analytical Model: no; Structural: no

# IfcSlab: Floor:NLRS_23_FL_Naturoll 037_260x580x3000mm, Floor:NLRS_23_FL_Naturoll 037_260x580x3000mm:13579
In: Begane grond
Type - PredefinedType: FLOOR; Material: Knauf Insulation_Ecose® glaswol_naturoll 037 260 mm
Type - Analytical Properties - Roughness: 1; Thermal mass: 0; Absorptance: 0.1; Heat Transfer Coefficient (U): 0.134615; Thermal Resistance (R): 7.42857
Type - Construction - Function: Interior; Default Thickness: 260 mm
Type - Graphics - Coarse Scale Fill Color: 0
Type - Identity Data - Type Image: Raster image: Naturoll 037.jpg (3); Assembly Code: 23; Assembly Description: Vloeren; Description: Naturoll 037 - 260mm; Manufacturer: Knauf Insulation B.V.; Model: Naturoll 037 is een onbeklede glaswoldeken met ECOSE® Technology; Type Name: NLRS_23_FL_Naturoll 037_260x580x3000mm; URL: www.knaufinsulation.nl
Type - Other - Category: Floors; Family Name: Floor
Type - Pset_ElementShading - Roughness: 304.8 mm
Type - Pset_ManufacturerTypeInformation - Manufacturer: Knauf Insulation B.V.
Type - Pset_ProductRequirements - Category: Floors
Type - Pset_QuantityTakeOff - Reference: NLRS_23_FL_Naturoll 037_260x580x3000mm
Type - Pset_ReinforcementBarPitchOfSlab - Description: Naturoll 037 - 260mm; Reference: NLRS_23_FL_Naturoll 037_260x580x3000mm
Type - Pset_SlabCommon - IsExternal: no; Reference: NLRS_23_FL_Naturoll 037_260x580x3000mm; ThermalTransmittance: 0.134615 kg/K/s3
Classification: 23 Vloeren (Uniformat)
Pset_SlabCommon - LoadBearing: no; PitchAngle: 0 deg
BaseQuantities - GrossArea: 1 m2; NetArea: 3.3 m2; GrossVolume: 260 m3; NetVolume: 0.26 m3; Perimeter: 5000 mm; Width: 260 mm
Constraints - Height Offset From Level: 0 mm; Related to Mass: no; Room Bounding: yes; Level: Level: Begane grond
Dimensions - Elevation at Top: 0 mm; Area: 1 m2; Elevation at Bottom: -260 mm; Perimeter: 5000 mm; Thickness: 260 mm; Volume: 0.26 m3
Other - Family: Floor: NLRS_23_FL_Naturoll 037_260x580x3000mm; Family and Type: Floor: NLRS_23_FL_Naturoll 037_260x580x3000mm; Type: Floor: NLRS_23_FL_Naturoll 037_260x580x3000mm; Type Id: Floor: NLRS_23_FL_Naturoll 037_260x580x3000mm
Phasing - Phase Created: New Construction
Structural - Enable Analytical Model: no; Structural: no

# IfcSlab: Floor:NLRS_23_FL_Naturoll 037_265x590x3000mm, Floor:NLRS_23_FL_Naturoll 037_265x590x3000mm:13717
In: Begane grond
Type - PredefinedType: FLOOR; Material: Knauf Insulation_Ecose® glaswol_naturoll 037 265 mm
Type - Analytical Properties - Roughness: 1; Thermal mass: 0; Absorptance: 0.1; Heat Transfer Coefficient (U): 0.132075; Thermal Resistance (R): 7.57143
Type - Construction - Function: Interior; Default Thickness: 265 mm
Type - Graphics - Coarse Scale Fill Color: 0
Type - Identity Data - Type Image: Raster image: Naturoll 037.jpg (3); Assembly Code: 23; Assembly Description: Vloeren; Description: Naturoll 037 - 265mm; Manufacturer: Knauf Insulation B.V.; Model: Naturoll 037 is een onbeklede glaswoldeken met ECOSE® Technology; Type Name: NLRS_23_FL_Naturoll 037_265x590x3000mm; URL: www.knaufinsulation.nl
Type - Other - Category: Floors; Family Name: Floor
Type - Pset_ElementShading - Roughness: 304.8 mm
Type - Pset_ManufacturerTypeInformation - Manufacturer: Knauf Insulation B.V.
Type - Pset_ProductRequirements - Category: Floors
Type - Pset_QuantityTakeOff - Reference: NLRS_23_FL_Naturoll 037_265x590x3000mm
Type - Pset_ReinforcementBarPitchOfSlab - Description: Naturoll 037 - 265mm; Reference: NLRS_23_FL_Naturoll 037_265x590x3000mm
Type - Pset_SlabCommon - IsExternal: no; Reference: NLRS_23_FL_Naturoll 037_265x590x3000mm; ThermalTransmittance: 0.132075 kg/K/s3
Classification: 23 Vloeren (Uniformat)
Pset_SlabCommon - LoadBearing: no; PitchAngle: 0 deg
BaseQuantities - GrossArea: 1 m2; NetArea: 3.325 m2; GrossVolume: 265 m3; NetVolume: 0.265 m3; Perimeter: 5000 mm; Width: 265 mm
Constraints - Height Offset From Level: 0 mm; Related to Mass: no; Room Bounding: yes; Level: Level: Begane grond
Dimensions - Elevation at Top: 0 mm; Area: 1 m2; Elevation at Bottom: -265 mm; Perimeter: 5000 mm; Thickness: 265 mm; Volume: 0.265 m3
Other - Family: Floor: NLRS_23_FL_Naturoll 037_265x590x3000mm; Family and Type: Floor: NLRS_23_FL_Naturoll 037_265x590x3000mm; Type: Floor: NLRS_23_FL_Naturoll 037_265x590x3000mm; Type Id: Floor: NLRS_23_FL_Naturoll 037_265x590x3000mm
Phasing - Phase Created: New Construction
Structural - Enable Analytical Model: no; Structural: no

# IfcSlab: Floor:NLRS_23_FL_Naturoll 037_90x380x8200mm, Floor:NLRS_23_FL_Naturoll 037_90x380x8200mm:11523
In: Begane grond
Type - PredefinedType: FLOOR; Material: Knauf Insulation_Ecose® glaswol_naturoll 037 90 mm
Type - Analytical Properties - Absorptance: 0.1; Heat Transfer Coefficient (U): 0.388889; Roughness: 1; Thermal mass: 0; Thermal Resistance (R): 2.57143
Type - Construction - Default Thickness: 90 mm; Function: Interior
Type - Graphics - Coarse Scale Fill Color: 0
Type - Identity Data - Assembly Code: 23; Assembly Description: Vloeren; Description: Naturoll 037 - 90mm; Manufacturer: Knauf Insulation B.V.; Model: Naturoll 037 is een onbeklede glaswoldeken met ECOSE® Technology; Type Image: Raster image: Naturoll 037.jpg (3); Type Name: NLRS_23_FL_Naturoll 037_90x380x8200mm; URL: www.knaufinsulation.nl
Type - Other - Category: Floors; Family Name: Floor
Type - Pset_ElementShading - Roughness: 304.8 mm
Type - Pset_ManufacturerTypeInformation - Manufacturer: Knauf Insulation B.V.
Type - Pset_ProductRequirements - Category: Floors
Type - Pset_QuantityTakeOff - Reference: NLRS_23_FL_Naturoll 037_90x380x8200mm
Type - Pset_ReinforcementBarPitchOfSlab - Description: Naturoll 037 - 90mm; Reference: NLRS_23_FL_Naturoll 037_90x380x8200mm
Type - Pset_SlabCommon - Reference: NLRS_23_FL_Naturoll 037_90x380x8200mm; IsExternal: no; ThermalTransmittance: 0.388889 kg/K/s3
Classification: 23 Vloeren (Uniformat)
Pset_SlabCommon - LoadBearing: no; PitchAngle: 0 deg
BaseQuantities - GrossArea: 1 m2; NetArea: 2.45 m2; GrossVolume: 90 m3; NetVolume: 0.09 m3; Perimeter: 5000 mm; Width: 90 mm
Constraints - Height Offset From Level: 0 mm; Level: Level: Begane grond; Related to Mass: no; Room Bounding: yes
Dimensions - Area: 1 m2; Elevation at Bottom: -90 mm; Elevation at Top: 0 mm; Perimeter: 5000 mm; Thickness: 90 mm; Volume: 0.09 m3
Other - Family: Floor: NLRS_23_FL_Naturoll 037_90x380x8200mm; Family and Type: Floor: NLRS_23_FL_Naturoll 037_90x380x8200mm; Type: Floor: NLRS_23_FL_Naturoll 037_90x380x8200mm; Type Id: Floor: NLRS_23_FL_Naturoll 037_90x380x8200mm
Phasing - Phase Created: New Construction
Structural - Enable Analytical Model: no; Structural: no

# IfcSlab: Floor:NLRS_23_FL_Naturoll 037_90x580x8200mm, Floor:NLRS_23_FL_Naturoll 037_90x580x8200mm:12977
In: Begane grond
Type - PredefinedType: FLOOR; Material: Knauf Insulation_Ecose® glaswol_naturoll 037 90 mm
Type - Analytical Properties - Roughness: 1; Thermal mass: 0; Absorptance: 0.1; Heat Transfer Coefficient (U): 0.388889; Thermal Resistance (R): 2.57143
Type - Construction - Function: Interior; Default Thickness: 90 mm
Type - Graphics - Coarse Scale Fill Color: 0
Type - Identity Data - Type Image: Raster image: Naturoll 037.jpg (3); Assembly Code: 23; Assembly Description: Vloeren; Description: Naturoll 037 - 90mm; Manufacturer: Knauf Insulation B.V.; Model: Naturoll 037 is een onbeklede glaswoldeken met ECOSE® Technology; Type Name: NLRS_23_FL_Naturoll 037_90x580x8200mm; URL: www.knaufinsulation.nl
Type - Other - Category: Floors; Family Name: Floor
Type - Pset_ElementShading - Roughness: 304.8 mm
Type - Pset_ManufacturerTypeInformation - Manufacturer: Knauf Insulation B.V.
Type - Pset_ProductRequirements - Category: Floors
Type - Pset_QuantityTakeOff - Reference: NLRS_23_FL_Naturoll 037_90x580x8200mm
Type - Pset_ReinforcementBarPitchOfSlab - Description: Naturoll 037 - 90mm; Reference: NLRS_23_FL_Naturoll 037_90x580x8200mm
Type - Pset_SlabCommon - IsExternal: no; Reference: NLRS_23_FL_Naturoll 037_90x580x8200mm; ThermalTransmittance: 0.388889 kg/K/s3
Classification: 23 Vloeren (Uniformat)
Pset_SlabCommon - LoadBearing: no; PitchAngle: 0 deg
BaseQuantities - GrossArea: 1 m2; NetArea: 2.45 m2; GrossVolume: 90 m3; NetVolume: 0.09 m3; Perimeter: 5000 mm; Width: 90 mm
Constraints - Height Offset From Level: 0 mm; Level: Level: Begane grond; Related to Mass: no; Room Bounding: yes
Dimensions - Elevation at Top: 0 mm; Area: 1 m2; Elevation at Bottom: -90 mm; Perimeter: 5000 mm; Thickness: 90 mm; Volume: 0.09 m3
Other - Family: Floor: NLRS_23_FL_Naturoll 037_90x580x8200mm; Family and Type: Floor: NLRS_23_FL_Naturoll 037_90x580x8200mm; Type: Floor: NLRS_23_FL_Naturoll 037_90x580x8200mm; Type Id: Floor: NLRS_23_FL_Naturoll 037_90x580x8200mm
Phasing - Phase Created: New Construction
Structural - Enable Analytical Model: no; Structural: no

# IfcWallStandardCase: Basic Wall:NLRS_21_WA_Naturoll 037_120x380x6500mm (2)
In: Begane grond
Type - PredefinedType: STANDARD; Material: Knauf Insulation_Ecose® glaswol_naturoll 037 120 mm
Type - Analytical Properties - Roughness: 1; Thermal mass: 0; Absorptance: 0.1; Heat Transfer Coefficient (U): 0.291667; Thermal Resistance (R): 3.42857
Type - Construction - Function: Exterior; Wrapping at Inserts: Do not wrap; Width: 120 mm
Type - Graphics - Coarse Scale Fill Color: 0
Type - Identity Data - Type Image: Raster image: Naturoll 037.jpg (3); Assembly Code: 21; Assembly Description: Buitenwanden; Description: Naturoll 037 - 120mm; Manufacturer: Knauf Insulation B.V.; Model: Naturoll 037 is een onbeklede glaswoldeken met ECOSE® Technology; Type Name: NLRS_21_WA_Naturoll 037_120x380x6500mm; URL: www.knaufinsulation.nl
Type - Other - Category: Walls; Family Name: Basic Wall
Type - Pset_ElementShading - Roughness: 304.8 mm
Type - Pset_ManufacturerTypeInformation - Manufacturer: Knauf Insulation B.V.
Type - Pset_ProductRequirements - Category: Walls
Type - Pset_QuantityTakeOff - Reference: NLRS_21_WA_Naturoll 037_120x380x6500mm
Type - Pset_ReinforcementBarPitchOfWall - Description: Naturoll 037 - 120mm; Reference: NLRS_21_WA_Naturoll 037_120x380x6500mm
Type - Pset_WallCommon - IsExternal: no; Reference: NLRS_21_WA_Naturoll 037_120x380x6500mm; ThermalTransmittance: 0.291667 kg/K/s3
Classification: 21 Buitenwanden (Uniformat)
BaseQuantities - Height: 2500 mm; Width: 120 mm
Constraints - Related to Mass: no; Room Bounding: yes; Base Constraint: Level: Begane grond; Base Extension Distance: 0 mm; Base is Attached: no; Base Offset: 0 mm; Top Constraint: Level: Lengte; Top Extension Distance: 0 mm; Top is Attached: no; Top Offset: 0 mm; Unconnected Height: 2500 mm
Other - Family: Basic Wall: NLRS_21_WA_Naturoll 037_120x380x6500mm; Family and Type: Basic Wall: NLRS_21_WA_Naturoll 037_120x380x6500mm; Type: Basic Wall: NLRS_21_WA_Naturoll 037_120x380x6500mm; Type Id: Basic Wall: NLRS_21_WA_Naturoll 037_120x380x6500mm
Phasing - Phase Created: New Construction
Structural - Enable Analytical Model: no; Structural: no; Structural Usage: Non-bearing
Pset_WallCommon - LoadBearing: no; IsExternal: yes; ExtendToStructure: no
Name (Basic Wall:NLRS_21_WA_Naturoll 037_120x380x6500mm:...) | BaseQuantities, Length (mm) = Dimensions, Length (mm) | GrossFootprintArea (m2) | NetVolume (m3) | NetSideArea (m2) | Location Line | Area (m2) | Volume (m3)
13034 | 2000 | 0.24 | 600000000 | 5000000 | Core Face: Interior | 5 | 0.6
13036 | 500 | 0.06 | 150000000 | 1250000 | Wall Centerline | 1.25 | 0.15

# IfcWallStandardCase: Basic Wall:NLRS_21_WA_Naturoll 037_120x580x6500mm (2)
In: Begane grond
Type - PredefinedType: STANDARD; Material: Knauf Insulation_Ecose® glaswol_naturoll 037 120 mm
Type - Analytical Properties - Roughness: 1; Thermal mass: 0; Absorptance: 0.1; Heat Transfer Coefficient (U): 0.291667; Thermal Resistance (R): 3.42857
Type - Construction - Function: Exterior; Wrapping at Inserts: Do not wrap; Width: 120 mm
Type - Graphics - Coarse Scale Fill Color: 0
Type - Identity Data - Type Image: Raster image: Naturoll 037.jpg (3); Assembly Code: 21; Assembly Description: Buitenwanden; Description: Naturoll 037 - 120mm; Manufacturer: Knauf Insulation B.V.; Model: Naturoll 037 is een onbeklede glaswoldeken met ECOSE® Technology; Type Name: NLRS_21_WA_Naturoll 037_120x580x6500mm; URL: www.knaufinsulation.nl
Type - Other - Category: Walls; Family Name: Basic Wall
Type - Pset_ElementShading - Roughness: 304.8 mm
Type - Pset_ManufacturerTypeInformation - Manufacturer: Knauf Insulation B.V.
Type - Pset_ProductRequirements - Category: Walls
Type - Pset_QuantityTakeOff - Reference: NLRS_21_WA_Naturoll 037_120x580x6500mm
Type - Pset_ReinforcementBarPitchOfWall - Description: Naturoll 037 - 120mm; Reference: NLRS_21_WA_Naturoll 037_120x580x6500mm
Type - Pset_WallCommon - IsExternal: no; Reference: NLRS_21_WA_Naturoll 037_120x580x6500mm; ThermalTransmittance: 0.291667 kg/K/s3
Classification: 21 Buitenwanden (Uniformat)
BaseQuantities - Height: 2500 mm; Width: 120 mm
Constraints - Related to Mass: no; Room Bounding: yes; Base Constraint: Level: Begane grond; Base Extension Distance: 0 mm; Base is Attached: no; Base Offset: 0 mm; Top Constraint: Level: Lengte; Top Extension Distance: 0 mm; Top is Attached: no; Top Offset: 0 mm; Unconnected Height: 2500 mm
Other - Family: Basic Wall: NLRS_21_WA_Naturoll 037_120x580x6500mm; Family and Type: Basic Wall: NLRS_21_WA_Naturoll 037_120x580x6500mm; Type: Basic Wall: NLRS_21_WA_Naturoll 037_120x580x6500mm; Type Id: Basic Wall: NLRS_21_WA_Naturoll 037_120x580x6500mm
Phasing - Phase Created: New Construction
Structural - Enable Analytical Model: no; Structural: no; Structural Usage: Non-bearing
Pset_WallCommon - LoadBearing: no; IsExternal: yes; ExtendToStructure: no
Name (Basic Wall:NLRS_21_WA_Naturoll 037_120x580x6500mm:...) | BaseQuantities, Length (mm) = Dimensions, Length (mm) | GrossFootprintArea (m2) | NetVolume (m3) | NetSideArea (m2) | Location Line | Area (m2) | Volume (m3)
13059 | 2000 | 0.24 | 600000000 | 5000000 | Core Face: Interior | 5 | 0.6
13061 | 500 | 0.06 | 150000000 | 1250000 | Wall Centerline | 1.25 | 0.15

# IfcWallStandardCase: Basic Wall:NLRS_21_WA_Naturoll 037_140x380x5600mm (2)
In: Begane grond
Type - PredefinedType: STANDARD; Material: Knauf Insulation_Ecose® glaswol_naturoll 037 140 mm
Type - Analytical Properties - Roughness: 1; Thermal mass: 0; Thermal Resistance (R): 4; Absorptance: 0.1; Heat Transfer Coefficient (U): 0.25
Type - Construction - Function: Exterior; Wrapping at Inserts: Do not wrap; Width: 140 mm
Type - Graphics - Coarse Scale Fill Color: 0
Type - Identity Data - Type Image: Raster image: Naturoll 037.jpg (3); Assembly Code: 21; Assembly Description: Buitenwanden; Description: Naturoll 037 - 140mm; Manufacturer: Knauf Insulation B.V.; Model: Naturoll 037 is een onbeklede glaswoldeken met ECOSE® Technology; Type Name: NLRS_21_WA_Naturoll 037_140x380x5600mm; URL: www.knaufinsulation.nl
Type - Other - Category: Walls; Family Name: Basic Wall
Type - Pset_ElementShading - Roughness: 304.8 mm
Type - Pset_ManufacturerTypeInformation - Manufacturer: Knauf Insulation B.V.
Type - Pset_ProductRequirements - Category: Walls
Type - Pset_QuantityTakeOff - Reference: NLRS_21_WA_Naturoll 037_140x380x5600mm
Type - Pset_ReinforcementBarPitchOfWall - Description: Naturoll 037 - 140mm; Reference: NLRS_21_WA_Naturoll 037_140x380x5600mm
Type - Pset_WallCommon - IsExternal: no; ThermalTransmittance: 0.25 kg/K/s3; Reference: NLRS_21_WA_Naturoll 037_140x380x5600mm
Classification: 21 Buitenwanden (Uniformat)
BaseQuantities - Height: 2500 mm; Width: 140 mm
Constraints - Related to Mass: no; Room Bounding: yes; Base Constraint: Level: Begane grond; Base Extension Distance: 0 mm; Base is Attached: no; Base Offset: 0 mm; Top Constraint: Level: Lengte; Top Extension Distance: 0 mm; Top is Attached: no; Top Offset: 0 mm; Unconnected Height: 2500 mm
Other - Family: Basic Wall: NLRS_21_WA_Naturoll 037_140x380x5600mm; Family and Type: Basic Wall: NLRS_21_WA_Naturoll 037_140x380x5600mm; Type: Basic Wall: NLRS_21_WA_Naturoll 037_140x380x5600mm; Type Id: Basic Wall: NLRS_21_WA_Naturoll 037_140x380x5600mm
Phasing - Phase Created: New Construction
Structural - Enable Analytical Model: no; Structural: no; Structural Usage: Non-bearing
Pset_WallCommon - LoadBearing: no; IsExternal: yes; ExtendToStructure: no
Name (Basic Wall:NLRS_21_WA_Naturoll 037_140x380x5600mm:...) | BaseQuantities, Length (mm) = Dimensions, Length (mm) | GrossFootprintArea (m2) | NetVolume (m3) | NetSideArea (m2) | Location Line | Area (m2) | Volume (m3)
13084 | 2000 | 0.28 | 700000000 | 5000000 | Core Face: Interior | 5 | 0.7
13086 | 500 | 0.07 | 175000000 | 1250000 | Wall Centerline | 1.25 | 0.175

# IfcWallStandardCase: Basic Wall:NLRS_21_WA_Naturoll 037_140x580x5600mm (2)
In: Begane grond
Type - PredefinedType: STANDARD; Material: Knauf Insulation_Ecose® glaswol_naturoll 037 140 mm
Type - Analytical Properties - Roughness: 1; Thermal mass: 0; Thermal Resistance (R): 4; Absorptance: 0.1; Heat Transfer Coefficient (U): 0.25
Type - Construction - Function: Exterior; Wrapping at Inserts: Do not wrap; Width: 140 mm
Type - Graphics - Coarse Scale Fill Color: 0
Type - Identity Data - Type Image: Raster image: Naturoll 037.jpg (3); Assembly Code: 21; Assembly Description: Buitenwanden; Description: Naturoll 037 - 140mm; Manufacturer: Knauf Insulation B.V.; Model: Naturoll 037 is een onbeklede glaswoldeken met ECOSE® Technology; Type Name: NLRS_21_WA_Naturoll 037_140x580x5600mm; URL: Knauf Insulation B.V.
Type - Other - Category: Walls; Family Name: Basic Wall
Type - Pset_ElementShading - Roughness: 304.8 mm
Type - Pset_ManufacturerTypeInformation - Manufacturer: Knauf Insulation B.V.
Type - Pset_ProductRequirements - Category: Walls
Type - Pset_QuantityTakeOff - Reference: NLRS_21_WA_Naturoll 037_140x580x5600mm
Type - Pset_ReinforcementBarPitchOfWall - Description: Naturoll 037 - 140mm; Reference: NLRS_21_WA_Naturoll 037_140x580x5600mm
Type - Pset_WallCommon - IsExternal: no; ThermalTransmittance: 0.25 kg/K/s3; Reference: NLRS_21_WA_Naturoll 037_140x580x5600mm
Classification: 21 Buitenwanden (Uniformat)
BaseQuantities - Height: 2500 mm; Width: 140 mm
Constraints - Related to Mass: no; Room Bounding: yes; Base Constraint: Level: Begane grond; Base Extension Distance: 0 mm; Base is Attached: no; Base Offset: 0 mm; Top Constraint: Level: Lengte; Top Extension Distance: 0 mm; Top is Attached: no; Top Offset: 0 mm; Unconnected Height: 2500 mm
Other - Family: Basic Wall: NLRS_21_WA_Naturoll 037_140x580x5600mm; Family and Type: Basic Wall: NLRS_21_WA_Naturoll 037_140x580x5600mm; Type: Basic Wall: NLRS_21_WA_Naturoll 037_140x580x5600mm; Type Id: Basic Wall: NLRS_21_WA_Naturoll 037_140x580x5600mm
Phasing - Phase Created: New Construction
Structural - Enable Analytical Model: no; Structural: no; Structural Usage: Non-bearing
Pset_WallCommon - LoadBearing: no; IsExternal: yes; ExtendToStructure: no
Name (Basic Wall:NLRS_21_WA_Naturoll 037_140x580x5600mm:...) | BaseQuantities, Length (mm) = Dimensions, Length (mm) | GrossFootprintArea (m2) | NetVolume (m3) | NetSideArea (m2) | Location Line | Area (m2) | Volume (m3)
13317 | 2000 | 0.28 | 700000000 | 5000000 | Core Face: Interior | 5 | 0.7
13319 | 500 | 0.07 | 175000000 | 1250000 | Wall Centerline | 1.25 | 0.175

# IfcWallStandardCase: Basic Wall:NLRS_21_WA_Naturoll 037_170x380x4600mm (2)
In: Begane grond
Type - PredefinedType: STANDARD; Material: Knauf Insulation_Ecose® glaswol_naturoll 037 170 mm
Type - Analytical Properties - Roughness: 1; Thermal mass: 0; Absorptance: 0.1; Heat Transfer Coefficient (U): 0.205882; Thermal Resistance (R): 4.85714
Type - Construction - Function: Exterior; Wrapping at Inserts: Do not wrap; Width: 170 mm
Type - Graphics - Coarse Scale Fill Color: 0
Type - Identity Data - Type Image: Raster image: Naturoll 037.jpg (3); Assembly Code: 21; Assembly Description: Buitenwanden; Description: Naturoll 037 - 170mm; Manufacturer: Knauf Insulation B.V.; Model: Naturoll 037 is een onbeklede glaswoldeken met ECOSE® Technology; Type Name: NLRS_21_WA_Naturoll 037_170x380x4600mm; URL: www.knaufinsulation.nl
Type - Other - Category: Walls; Family Name: Basic Wall
Type - Pset_ElementShading - Roughness: 304.8 mm
Type - Pset_ManufacturerTypeInformation - Manufacturer: Knauf Insulation B.V.
Type - Pset_ProductRequirements - Category: Walls
Type - Pset_QuantityTakeOff - Reference: NLRS_21_WA_Naturoll 037_170x380x4600mm
Type - Pset_ReinforcementBarPitchOfWall - Description: Naturoll 037 - 170mm; Reference: NLRS_21_WA_Naturoll 037_170x380x4600mm
Type - Pset_WallCommon - IsExternal: no; Reference: NLRS_21_WA_Naturoll 037_170x380x4600mm; ThermalTransmittance: 0.205882 kg/K/s3
Classification: 21 Buitenwanden (Uniformat)
BaseQuantities - Height: 2500 mm; Width: 170 mm
Constraints - Related to Mass: no; Room Bounding: yes; Base Constraint: Level: Begane grond; Base Extension Distance: 0 mm; Base is Attached: no; Base Offset: 0 mm; Top Constraint: Level: Lengte; Top Extension Distance: 0 mm; Top is Attached: no; Top Offset: 0 mm; Unconnected Height: 2500 mm
Other - Family: Basic Wall: NLRS_21_WA_Naturoll 037_170x380x4600mm; Family and Type: Basic Wall: NLRS_21_WA_Naturoll 037_170x380x4600mm; Type: Basic Wall: NLRS_21_WA_Naturoll 037_170x380x4600mm; Type Id: Basic Wall: NLRS_21_WA_Naturoll 037_170x380x4600mm
Phasing - Phase Created: New Construction
Structural - Enable Analytical Model: no; Structural: no; Structural Usage: Non-bearing
Pset_WallCommon - LoadBearing: no; IsExternal: yes; ExtendToStructure: no
Name (Basic Wall:NLRS_21_WA_Naturoll 037_170x380x4600mm:...) | BaseQuantities, Length (mm) = Dimensions, Length (mm) | GrossFootprintArea (m2) | NetVolume (m3) | NetSideArea (m2) | Location Line | Area (m2) | Volume (m3)
13339 | 2000 | 0.34 | 850000000 | 5000000 | Core Face: Interior | 5 | 0.85
13341 | 500 | 0.085 | 212500000 | 1250000 | Wall Centerline | 1.25 | 0.2125

# IfcWallStandardCase: Basic Wall:NLRS_21_WA_Naturoll 037_170x580x4600mm (2)
In: Begane grond
Type - PredefinedType: STANDARD; Material: Knauf Insulation_Ecose® glaswol_naturoll 037 170 mm
Type - Analytical Properties - Roughness: 1; Thermal mass: 0; Absorptance: 0.1; Heat Transfer Coefficient (U): 0.205882; Thermal Resistance (R): 4.85714
Type - Construction - Function: Exterior; Wrapping at Inserts: Do not wrap; Width: 170 mm
Type - Graphics - Coarse Scale Fill Color: 0
Type - Identity Data - Type Image: Raster image: Naturoll 037.jpg (3); Assembly Code: 21; Assembly Description: Buitenwanden; Description: Naturoll 037 - 170mm; Manufacturer: Knauf Insulation B.V.; Model: Naturoll 037 is een onbeklede glaswoldeken met ECOSE® Technology; Type Name: NLRS_21_WA_Naturoll 037_170x580x4600mm; URL: www.knaufinsulation.nl
Type - Other - Category: Walls; Family Name: Basic Wall
Type - Pset_ElementShading - Roughness: 304.8 mm
Type - Pset_ManufacturerTypeInformation - Manufacturer: Knauf Insulation B.V.
Type - Pset_ProductRequirements - Category: Walls
Type - Pset_QuantityTakeOff - Reference: NLRS_21_WA_Naturoll 037_170x580x4600mm
Type - Pset_ReinforcementBarPitchOfWall - Description: Naturoll 037 - 170mm; Reference: NLRS_21_WA_Naturoll 037_170x580x4600mm
Type - Pset_WallCommon - IsExternal: no; Reference: NLRS_21_WA_Naturoll 037_170x580x4600mm; ThermalTransmittance: 0.205882 kg/K/s3
Classification: 21 Buitenwanden (Uniformat)
BaseQuantities - Height: 2500 mm; Width: 170 mm
Constraints - Related to Mass: no; Room Bounding: yes; Base Constraint: Level: Begane grond; Base Extension Distance: 0 mm; Base is Attached: no; Base Offset: 0 mm; Top Constraint: Level: Lengte; Top Extension Distance: 0 mm; Top is Attached: no; Top Offset: 0 mm; Unconnected Height: 2500 mm
Other - Family: Basic Wall: NLRS_21_WA_Naturoll 037_170x580x4600mm; Family and Type: Basic Wall: NLRS_21_WA_Naturoll 037_170x580x4600mm; Type: Basic Wall: NLRS_21_WA_Naturoll 037_170x580x4600mm; Type Id: Basic Wall: NLRS_21_WA_Naturoll 037_170x580x4600mm
Phasing - Phase Created: New Construction
Structural - Enable Analytical Model: no; Structural: no; Structural Usage: Non-bearing
Pset_WallCommon - LoadBearing: no; IsExternal: yes; ExtendToStructure: no
Name (Basic Wall:NLRS_21_WA_Naturoll 037_170x580x4600mm:...) | BaseQuantities, Length (mm) = Dimensions, Length (mm) | GrossFootprintArea (m2) | NetVolume (m3) | NetSideArea (m2) | Location Line | Area (m2) | Volume (m3)
13361 | 2000 | 0.34 | 850000000 | 5000000 | Core Face: Interior | 5 | 0.85
13363 | 500 | 0.085 | 212500000 | 1250000 | Wall Centerline | 1.25 | 0.2125

# IfcWallStandardCase: Basic Wall:NLRS_21_WA_Naturoll 037_170x590x4600mm (2)
In: Begane grond
Type - PredefinedType: STANDARD; Material: Knauf Insulation_Ecose® glaswol_naturoll 037 170 mm
Type - Analytical Properties - Roughness: 1; Thermal mass: 0; Absorptance: 0.1; Heat Transfer Coefficient (U): 0.205882; Thermal Resistance (R): 4.85714
Type - Construction - Function: Exterior; Wrapping at Inserts: Do not wrap; Width: 170 mm
Type - Graphics - Coarse Scale Fill Color: 0
Type - Identity Data - Type Image: Raster image: Naturoll 037.jpg (3); Assembly Code: 21; Assembly Description: Buitenwanden; Description: Naturoll 037 - 170mm; Manufacturer: Knauf Insulation B.V.; Model: Naturoll 037 is een onbeklede glaswoldeken met ECOSE® Technology; Type Name: NLRS_21_WA_Naturoll 037_170x590x4600mm; URL: www.knaufinsulation.nl
Type - Other - Category: Walls; Family Name: Basic Wall
Type - Pset_ElementShading - Roughness: 304.8 mm
Type - Pset_ManufacturerTypeInformation - Manufacturer: Knauf Insulation B.V.
Type - Pset_ProductRequirements - Category: Walls
Type - Pset_QuantityTakeOff - Reference: NLRS_21_WA_Naturoll 037_170x590x4600mm
Type - Pset_ReinforcementBarPitchOfWall - Description: Naturoll 037 - 170mm; Reference: NLRS_21_WA_Naturoll 037_170x590x4600mm
Type - Pset_WallCommon - IsExternal: no; Reference: NLRS_21_WA_Naturoll 037_170x590x4600mm; ThermalTransmittance: 0.205882 kg/K/s3
Classification: 21 Buitenwanden (Uniformat)
BaseQuantities - Height: 2500 mm; Width: 170 mm
Constraints - Related to Mass: no; Room Bounding: yes; Base Constraint: Level: Begane grond; Base Extension Distance: 0 mm; Base is Attached: no; Base Offset: 0 mm; Top Constraint: Level: Lengte; Top Extension Distance: 0 mm; Top is Attached: no; Top Offset: 0 mm; Unconnected Height: 2500 mm
Other - Family: Basic Wall: NLRS_21_WA_Naturoll 037_170x590x4600mm; Family and Type: Basic Wall: NLRS_21_WA_Naturoll 037_170x590x4600mm; Type: Basic Wall: NLRS_21_WA_Naturoll 037_170x590x4600mm; Type Id: Basic Wall: NLRS_21_WA_Naturoll 037_170x590x4600mm
Phasing - Phase Created: New Construction
Structural - Enable Analytical Model: no; Structural: no; Structural Usage: Non-bearing
Pset_WallCommon - LoadBearing: no; IsExternal: yes; ExtendToStructure: no
Name (Basic Wall:NLRS_21_WA_Naturoll 037_170x590x4600mm:...) | BaseQuantities, Length (mm) = Dimensions, Length (mm) | GrossFootprintArea (m2) | NetVolume (m3) | NetSideArea (m2) | Location Line | Area (m2) | Volume (m3)
13383 | 2000 | 0.34 | 850000000 | 5000000 | Core Face: Interior | 5 | 0.85
13385 | 500 | 0.085 | 212500000 | 1250000 | Wall Centerline | 1.25 | 0.2125

# IfcWallStandardCase: Basic Wall:NLRS_21_WA_Naturoll 037_190x580x4100mm (2)
In: Begane grond
Type - PredefinedType: STANDARD; Material: Knauf Insulation_Ecose® glaswol_naturoll 037 190 mm
Type - Analytical Properties - Roughness: 1; Thermal mass: 0; Absorptance: 0.1; Heat Transfer Coefficient (U): 0.184211; Thermal Resistance (R): 5.42857
Type - Construction - Function: Exterior; Wrapping at Inserts: Do not wrap; Width: 190 mm
Type - Graphics - Coarse Scale Fill Color: 0
Type - Identity Data - Type Image: Raster image: Naturoll 037.jpg (3); Assembly Code: 21; Assembly Description: Buitenwanden; Description: Naturoll 037 - 190mm; Manufacturer: Knauf Insulation B.V.; Model: Naturoll 037 is een onbeklede glaswoldeken met ECOSE® Technology; Type Name: NLRS_21_WA_Naturoll 037_190x580x4100mm; URL: www.knaufinsulation.nl
Type - Other - Category: Walls; Family Name: Basic Wall
Type - Pset_ElementShading - Roughness: 304.8 mm
Type - Pset_ManufacturerTypeInformation - Manufacturer: Knauf Insulation B.V.
Type - Pset_ProductRequirements - Category: Walls
Type - Pset_QuantityTakeOff - Reference: NLRS_21_WA_Naturoll 037_190x580x4100mm
Type - Pset_ReinforcementBarPitchOfWall - Description: Naturoll 037 - 190mm; Reference: NLRS_21_WA_Naturoll 037_190x580x4100mm
Type - Pset_WallCommon - IsExternal: no; Reference: NLRS_21_WA_Naturoll 037_190x580x4100mm; ThermalTransmittance: 0.184211 kg/K/s3
Classification: 21 Buitenwanden (Uniformat)
BaseQuantities - Height: 2500 mm; Width: 190 mm
Constraints - Related to Mass: no; Room Bounding: yes; Base Constraint: Level: Begane grond; Base Extension Distance: 0 mm; Base is Attached: no; Base Offset: 0 mm; Top Constraint: Level: Lengte; Top Extension Distance: 0 mm; Top is Attached: no; Top Offset: 0 mm; Unconnected Height: 2500 mm
Other - Family: Basic Wall: NLRS_21_WA_Naturoll 037_190x580x4100mm; Family and Type: Basic Wall: NLRS_21_WA_Naturoll 037_190x580x4100mm; Type: Basic Wall: NLRS_21_WA_Naturoll 037_190x580x4100mm; Type Id: Basic Wall: NLRS_21_WA_Naturoll 037_190x580x4100mm
Phasing - Phase Created: New Construction
Structural - Enable Analytical Model: no; Structural: no; Structural Usage: Non-bearing
Pset_WallCommon - LoadBearing: no; IsExternal: yes; ExtendToStructure: no
Name (Basic Wall:NLRS_21_WA_Naturoll 037_190x580x4100mm:...) | BaseQuantities, Length (mm) = Dimensions, Length (mm) | GrossFootprintArea (m2) | NetVolume (m3) | NetSideArea (m2) | Location Line | Area (m2) | Volume (m3)
13405 | 2000 | 0.38 | 950000000 | 5000000 | Core Face: Interior | 5 | 0.95
13407 | 500 | 0.095 | 237500000 | 1250000 | Wall Centerline | 1.25 | 0.2375

# IfcWallStandardCase: Basic Wall:NLRS_21_WA_Naturoll 037_190x590x4100mm (2)
In: Begane grond
Type - PredefinedType: STANDARD; Material: Knauf Insulation_Ecose® glaswol_naturoll 037 190 mm
Type - Analytical Properties - Roughness: 1; Thermal mass: 0; Absorptance: 0.1; Heat Transfer Coefficient (U): 0.184211; Thermal Resistance (R): 5.42857
Type - Construction - Function: Exterior; Wrapping at Inserts: Do not wrap; Width: 190 mm
Type - Graphics - Coarse Scale Fill Color: 0
Type - Identity Data - Type Image: Raster image: Naturoll 037.jpg (3); Assembly Code: 21; Assembly Description: Buitenwanden; Description: Naturoll 037 - 190mm; Manufacturer: Knauf Insulation B.V.; Model: Naturoll 037 is een onbeklede glaswoldeken met ECOSE® Technology; Type Name: NLRS_21_WA_Naturoll 037_190x590x4100mm; URL: www.knaufinsulation.nl
Type - Other - Category: Walls; Family Name: Basic Wall
Type - Pset_ElementShading - Roughness: 304.8 mm
Type - Pset_ManufacturerTypeInformation - Manufacturer: Knauf Insulation B.V.
Type - Pset_ProductRequirements - Category: Walls
Type - Pset_QuantityTakeOff - Reference: NLRS_21_WA_Naturoll 037_190x590x4100mm
Type - Pset_ReinforcementBarPitchOfWall - Description: Naturoll 037 - 190mm; Reference: NLRS_21_WA_Naturoll 037_190x590x4100mm
Type - Pset_WallCommon - IsExternal: no; Reference: NLRS_21_WA_Naturoll 037_190x590x4100mm; ThermalTransmittance: 0.184211 kg/K/s3
Classification: 21 Buitenwanden (Uniformat)
BaseQuantities - Height: 2500 mm; Width: 190 mm
Constraints - Related to Mass: no; Room Bounding: yes; Base Constraint: Level: Begane grond; Base Extension Distance: 0 mm; Base is Attached: no; Base Offset: 0 mm; Top Constraint: Level: Lengte; Top Extension Distance: 0 mm; Top is Attached: no; Top Offset: 0 mm; Unconnected Height: 2500 mm
Other - Family: Basic Wall: NLRS_21_WA_Naturoll 037_190x590x4100mm; Family and Type: Basic Wall: NLRS_21_WA_Naturoll 037_190x590x4100mm; Type: Basic Wall: NLRS_21_WA_Naturoll 037_190x590x4100mm; Type Id: Basic Wall: NLRS_21_WA_Naturoll 037_190x590x4100mm
Phasing - Phase Created: New Construction
Structural - Enable Analytical Model: no; Structural: no; Structural Usage: Non-bearing
Pset_WallCommon - LoadBearing: no; IsExternal: yes; ExtendToStructure: no
Name (Basic Wall:NLRS_21_WA_Naturoll 037_190x590x4100mm:...) | BaseQuantities, Length (mm) = Dimensions, Length (mm) | GrossFootprintArea (m2) | NetVolume (m3) | NetSideArea (m2) | Location Line | Area (m2) | Volume (m3)
13504 | 2000 | 0.38 | 950000000 | 5000000 | Core Face: Interior | 5 | 0.95
13506 | 500 | 0.095 | 237500000 | 1250000 | Wall Centerline | 1.25 | 0.2375

# IfcWallStandardCase: Basic Wall:NLRS_21_WA_Naturoll 037_220x580x3500mm (2)
In: Begane grond
Type - PredefinedType: STANDARD; Material: Knauf Insulation_Ecose® glaswol_naturoll 037 220 mm
Type - Analytical Properties - Roughness: 1; Thermal mass: 0; Absorptance: 0.1; Heat Transfer Coefficient (U): 0.159091; Thermal Resistance (R): 6.28571
Type - Construction - Function: Exterior; Wrapping at Inserts: Do not wrap; Width: 220 mm
Type - Graphics - Coarse Scale Fill Color: 0
Type - Identity Data - Type Image: Raster image: Naturoll 037.jpg (3); Assembly Code: 21; Assembly Description: Buitenwanden; Description: Naturoll 037 - 220mm; Manufacturer: Knauf Insulation B.V.; Model: Naturoll 037 is een onbeklede glaswoldeken met ECOSE® Technology; Type Name: NLRS_21_WA_Naturoll 037_220x580x3500mm; URL: www.knaufinsulation.nl
Type - Other - Category: Walls; Family Name: Basic Wall
Type - Pset_ElementShading - Roughness: 304.8 mm
Type - Pset_ManufacturerTypeInformation - Manufacturer: Knauf Insulation B.V.
Type - Pset_ProductRequirements - Category: Walls
Type - Pset_QuantityTakeOff - Reference: NLRS_21_WA_Naturoll 037_220x580x3500mm
Type - Pset_ReinforcementBarPitchOfWall - Description: Naturoll 037 - 220mm; Reference: NLRS_21_WA_Naturoll 037_220x580x3500mm
Type - Pset_WallCommon - IsExternal: no; Reference: NLRS_21_WA_Naturoll 037_220x580x3500mm; ThermalTransmittance: 0.159091 kg/K/s3
Classification: 21 Buitenwanden (Uniformat)
BaseQuantities - Height: 2500 mm; Width: 220 mm
Constraints - Related to Mass: no; Room Bounding: yes; Base Constraint: Level: Begane grond; Base Extension Distance: 0 mm; Base is Attached: no; Base Offset: 0 mm; Top Constraint: Level: Lengte; Top Extension Distance: 0 mm; Top is Attached: no; Top Offset: 0 mm; Unconnected Height: 2500 mm
Other - Family: Basic Wall: NLRS_21_WA_Naturoll 037_220x580x3500mm; Family and Type: Basic Wall: NLRS_21_WA_Naturoll 037_220x580x3500mm; Type: Basic Wall: NLRS_21_WA_Naturoll 037_220x580x3500mm; Type Id: Basic Wall: NLRS_21_WA_Naturoll 037_220x580x3500mm
Phasing - Phase Created: New Construction
Structural - Enable Analytical Model: no; Structural: no; Structural Usage: Non-bearing
Pset_WallCommon - LoadBearing: no; IsExternal: yes; ExtendToStructure: no
Name (Basic Wall:NLRS_21_WA_Naturoll 037_220x580x3500mm:...) | BaseQuantities, Length (mm) = Dimensions, Length (mm) | GrossFootprintArea (m2) | NetVolume (m3) | NetSideArea (m2) | Location Line | Area (m2) | Volume (m3)
13524 | 2000 | 0.44 | 1100000000 | 5000000 | Core Face: Interior | 5 | 1.1
13526 | 500 | 0.11 | 275000000 | 1250000 | Wall Centerline | 1.25 | 0.275

# IfcWallStandardCase: Basic Wall:NLRS_21_WA_Naturoll 037_220x590x3500mm (2)
In: Begane grond
Type - PredefinedType: STANDARD; Material: Knauf Insulation_Ecose® glaswol_naturoll 037 220 mm
Type - Analytical Properties - Roughness: 1; Thermal mass: 0; Absorptance: 0.1; Heat Transfer Coefficient (U): 0.159091; Thermal Resistance (R): 6.28571
Type - Construction - Function: Exterior; Wrapping at Inserts: Do not wrap; Width: 220 mm
Type - Graphics - Coarse Scale Fill Color: 0
Type - Identity Data - Type Image: Raster image: Naturoll 037.jpg (3); Assembly Code: 21; Assembly Description: Buitenwanden; Description: Naturoll 037 - 220mm; Manufacturer: Knauf Insulation B.V.; Model: Naturoll 037 is een onbeklede glaswoldeken met ECOSE® Technology; Type Name: NLRS_21_WA_Naturoll 037_220x590x3500mm; URL: www.knaufinsulation.nl
Type - Other - Category: Walls; Family Name: Basic Wall
Type - Pset_ElementShading - Roughness: 304.8 mm
Type - Pset_ManufacturerTypeInformation - Manufacturer: Knauf Insulation B.V.
Type - Pset_ProductRequirements - Category: Walls
Type - Pset_QuantityTakeOff - Reference: NLRS_21_WA_Naturoll 037_220x590x3500mm
Type - Pset_ReinforcementBarPitchOfWall - Description: Naturoll 037 - 220mm; Reference: NLRS_21_WA_Naturoll 037_220x590x3500mm
Type - Pset_WallCommon - IsExternal: no; Reference: NLRS_21_WA_Naturoll 037_220x590x3500mm; ThermalTransmittance: 0.159091 kg/K/s3
Classification: 21 Buitenwanden (Uniformat)
BaseQuantities - Height: 2500 mm; Width: 220 mm
Constraints - Related to Mass: no; Room Bounding: yes; Base Constraint: Level: Begane grond; Base Extension Distance: 0 mm; Base is Attached: no; Base Offset: 0 mm; Top Constraint: Level: Lengte; Top Extension Distance: 0 mm; Top is Attached: no; Top Offset: 0 mm; Unconnected Height: 2500 mm
Other - Family: Basic Wall: NLRS_21_WA_Naturoll 037_220x590x3500mm; Family and Type: Basic Wall: NLRS_21_WA_Naturoll 037_220x590x3500mm; Type: Basic Wall: NLRS_21_WA_Naturoll 037_220x590x3500mm; Type Id: Basic Wall: NLRS_21_WA_Naturoll 037_220x590x3500mm
Phasing - Phase Created: New Construction
Structural - Enable Analytical Model: no; Structural: no; Structural Usage: Non-bearing
Pset_WallCommon - LoadBearing: no; IsExternal: yes; ExtendToStructure: no
Name (Basic Wall:NLRS_21_WA_Naturoll 037_220x590x3500mm:...) | BaseQuantities, Length (mm) = Dimensions, Length (mm) | GrossFootprintArea (m2) | NetVolume (m3) | NetSideArea (m2) | Location Line | Area (m2) | Volume (m3)
13544 | 2000 | 0.44 | 1100000000 | 5000000 | Core Face: Interior | 5 | 1.1
13546 | 500 | 0.11 | 275000000 | 1250000 | Wall Centerline | 1.25 | 0.275

# IfcWallStandardCase: Basic Wall:NLRS_21_WA_Naturoll 037_240x590x3250mm (2)
In: Begane grond
Type - PredefinedType: STANDARD; Material: Knauf Insulation_Ecose® glaswol_naturoll 037 240 mm
Type - Analytical Properties - Roughness: 1; Thermal mass: 0; Absorptance: 0.1; Heat Transfer Coefficient (U): 0.145833; Thermal Resistance (R): 6.85714
Type - Construction - Function: Exterior; Wrapping at Inserts: Do not wrap; Width: 240 mm
Type - Graphics - Coarse Scale Fill Color: 0
Type - Identity Data - Type Image: Raster image: Naturoll 037.jpg (3); Assembly Code: 21; Assembly Description: Buitenwanden; Description: Naturoll 037 - 240mm; Manufacturer: Knauf Insulation B.V.; Model: Naturoll 037 is een onbeklede glaswoldeken met ECOSE® Technology; Type Name: NLRS_21_WA_Naturoll 037_240x590x3250mm; URL: www.knaufinsulation.nl
Type - Other - Category: Walls; Family Name: Basic Wall
Type - Pset_ElementShading - Roughness: 304.8 mm
Type - Pset_ManufacturerTypeInformation - Manufacturer: Knauf Insulation B.V.
Type - Pset_ProductRequirements - Category: Walls
Type - Pset_QuantityTakeOff - Reference: NLRS_21_WA_Naturoll 037_240x590x3250mm
Type - Pset_ReinforcementBarPitchOfWall - Description: Naturoll 037 - 240mm; Reference: NLRS_21_WA_Naturoll 037_240x590x3250mm
Type - Pset_WallCommon - IsExternal: no; Reference: NLRS_21_WA_Naturoll 037_240x590x3250mm; ThermalTransmittance: 0.145833 kg/K/s3
Classification: 21 Buitenwanden (Uniformat)
BaseQuantities - Height: 2500 mm; Width: 240 mm
Constraints - Related to Mass: no; Room Bounding: yes; Base Constraint: Level: Begane grond; Base Extension Distance: 0 mm; Base is Attached: no; Base Offset: 0 mm; Top Constraint: Level: Lengte; Top Extension Distance: 0 mm; Top is Attached: no; Top Offset: 0 mm; Unconnected Height: 2500 mm
Other - Family: Basic Wall: NLRS_21_WA_Naturoll 037_240x590x3250mm; Family and Type: Basic Wall: NLRS_21_WA_Naturoll 037_240x590x3250mm; Type: Basic Wall: NLRS_21_WA_Naturoll 037_240x590x3250mm; Type Id: Basic Wall: NLRS_21_WA_Naturoll 037_240x590x3250mm
Phasing - Phase Created: New Construction
Structural - Enable Analytical Model: no; Structural: no; Structural Usage: Non-bearing
Pset_WallCommon - LoadBearing: no; IsExternal: yes; ExtendToStructure: no
Name (Basic Wall:NLRS_21_WA_Naturoll 037_240x590x3250mm:...) | BaseQuantities, Length (mm) = Dimensions, Length (mm) | GrossFootprintArea (m2) | NetVolume (m3) | NetSideArea (m2) | Location Line | Area (m2) | Volume (m3)
13564 | 2000 | 0.48 | 1200000000 | 5000000 | Core Face: Interior | 5 | 1.2
13566 | 500 | 0.12 | 300000000 | 1250000 | Wall Centerline | 1.25 | 0.3

# IfcWallStandardCase: Basic Wall:NLRS_21_WA_Naturoll 037_260x580x3000mm (2)
In: Begane grond
Type - PredefinedType: STANDARD; Material: Knauf Insulation_Ecose® glaswol_naturoll 037 260 mm
Type - Analytical Properties - Roughness: 1; Thermal mass: 0; Absorptance: 0.1; Heat Transfer Coefficient (U): 0.134615; Thermal Resistance (R): 7.42857
Type - Construction - Function: Exterior; Wrapping at Inserts: Do not wrap; Width: 260 mm
Type - Graphics - Coarse Scale Fill Color: 0
Type - Identity Data - Type Image: Raster image: Naturoll 037.jpg (3); Assembly Code: 21; Assembly Description: Buitenwanden; Description: Naturoll 037 - 260mm; Manufacturer: Knauf Insulation B.V.; Model: Naturoll 037 is een onbeklede glaswoldeken met ECOSE® Technology; Type Name: NLRS_21_WA_Naturoll 037_260x580x3000mm; URL: www.knaufinsulation.nl
Type - Other - Category: Walls; Family Name: Basic Wall
Type - Pset_ElementShading - Roughness: 304.8 mm
Type - Pset_ManufacturerTypeInformation - Manufacturer: Knauf Insulation B.V.
Type - Pset_ProductRequirements - Category: Walls
Type - Pset_QuantityTakeOff - Reference: NLRS_21_WA_Naturoll 037_260x580x3000mm
Type - Pset_ReinforcementBarPitchOfWall - Description: Naturoll 037 - 260mm; Reference: NLRS_21_WA_Naturoll 037_260x580x3000mm
Type - Pset_WallCommon - IsExternal: no; Reference: NLRS_21_WA_Naturoll 037_260x580x3000mm; ThermalTransmittance: 0.134615 kg/K/s3
Classification: 21 Buitenwanden (Uniformat)
BaseQuantities - Height: 2500 mm; Width: 260 mm
Constraints - Related to Mass: no; Room Bounding: yes; Base Constraint: Level: Begane grond; Base Extension Distance: 0 mm; Base is Attached: no; Base Offset: 0 mm; Top Constraint: Level: Lengte; Top Extension Distance: 0 mm; Top is Attached: no; Top Offset: 0 mm; Unconnected Height: 2500 mm
Other - Family: Basic Wall: NLRS_21_WA_Naturoll 037_260x580x3000mm; Family and Type: Basic Wall: NLRS_21_WA_Naturoll 037_260x580x3000mm; Type: Basic Wall: NLRS_21_WA_Naturoll 037_260x580x3000mm; Type Id: Basic Wall: NLRS_21_WA_Naturoll 037_260x580x3000mm
Phasing - Phase Created: New Construction
Structural - Enable Analytical Model: no; Structural: no; Structural Usage: Non-bearing
Pset_WallCommon - LoadBearing: no; IsExternal: yes; ExtendToStructure: no
Name (Basic Wall:NLRS_21_WA_Naturoll 037_260x580x3000mm:...) | BaseQuantities, Length (mm) = Dimensions, Length (mm) | GrossFootprintArea (m2) | NetVolume (m3) | NetSideArea (m2) | Location Line | Area (m2) | Volume (m3)
13584 | 2000 | 0.52 | 1300000000 | 5000000 | Core Face: Interior | 5 | 1.3
13586 | 500 | 0.13 | 325000000 | 1250000 | Wall Centerline | 1.25 | 0.325

# IfcWallStandardCase: Basic Wall:NLRS_21_WA_Naturoll 037_265x590x3000mm (2)
In: Begane grond
Type - PredefinedType: STANDARD; Material: Knauf Insulation_Ecose® glaswol_naturoll 037 265 mm
Type - Analytical Properties - Roughness: 1; Thermal mass: 0; Absorptance: 0.1; Heat Transfer Coefficient (U): 0.132075; Thermal Resistance (R): 7.57143
Type - Construction - Function: Exterior; Wrapping at Inserts: Do not wrap; Width: 265 mm
Type - Graphics - Coarse Scale Fill Color: 0
Type - Identity Data - Type Image: Raster image: Naturoll 037.jpg (3); Assembly Code: 21; Assembly Description: Buitenwanden; Description: Naturoll 037 - 265mm; Manufacturer: Knauf Insulation B.V.; Model: Naturoll 037 is een onbeklede glaswoldeken met ECOSE® Technology; Type Name: NLRS_21_WA_Naturoll 037_265x590x3000mm; URL: www.knaufinsulation.nl
Type - Other - Category: Walls; Family Name: Basic Wall
Type - Pset_ElementShading - Roughness: 304.8 mm
Type - Pset_ManufacturerTypeInformation - Manufacturer: Knauf Insulation B.V.
Type - Pset_ProductRequirements - Category: Walls
Type - Pset_QuantityTakeOff - Reference: NLRS_21_WA_Naturoll 037_265x590x3000mm
Type - Pset_ReinforcementBarPitchOfWall - Description: Naturoll 037 - 265mm; Reference: NLRS_21_WA_Naturoll 037_265x590x3000mm
Type - Pset_WallCommon - IsExternal: no; Reference: NLRS_21_WA_Naturoll 037_265x590x3000mm; ThermalTransmittance: 0.132075 kg/K/s3
Classification: 21 Buitenwanden (Uniformat)
BaseQuantities - Height: 2500 mm; Width: 265 mm
Constraints - Related to Mass: no; Room Bounding: yes; Base Constraint: Level: Begane grond; Base Extension Distance: 0 mm; Base is Attached: no; Base Offset: 0 mm; Top Constraint: Level: Lengte; Top Extension Distance: 0 mm; Top is Attached: no; Top Offset: 0 mm; Unconnected Height: 2500 mm
Other - Family: Basic Wall: NLRS_21_WA_Naturoll 037_265x590x3000mm; Family and Type: Basic Wall: NLRS_21_WA_Naturoll 037_265x590x3000mm; Type: Basic Wall: NLRS_21_WA_Naturoll 037_265x590x3000mm; Type Id: Basic Wall: NLRS_21_WA_Naturoll 037_265x590x3000mm
Phasing - Phase Created: New Construction
Structural - Enable Analytical Model: no; Structural: no; Structural Usage: Non-bearing
Pset_WallCommon - LoadBearing: no; IsExternal: yes; ExtendToStructure: no
Name (Basic Wall:NLRS_21_WA_Naturoll 037_265x590x3000mm:...) | BaseQuantities, Length (mm) = Dimensions, Length (mm) | GrossFootprintArea (m2) | NetVolume (m3) | NetSideArea (m2) | Location Line | Area (m2) | Volume (m3)
13722 | 2000 | 0.53 | 1325000000 | 5000000 | Core Face: Interior | 5 | 1.325
13724 | 500 | 0.1325 | 331250000 | 1250000 | Wall Centerline | 1.25 | 0.33125

# IfcWallStandardCase: Basic Wall:NLRS_21_WA_Naturoll 037_90x380x8200mm (2)
In: Begane grond
Type - PredefinedType: STANDARD; Material: Knauf Insulation_Ecose® glaswol_naturoll 037 90 mm
Type - Analytical Properties - Roughness: 1; Thermal mass: 0; Absorptance: 0.1; Heat Transfer Coefficient (U): 0.388889; Thermal Resistance (R): 2.57143
Type - Construction - Function: Exterior; Width: 90 mm; Wrapping at Inserts: Do not wrap
Type - Graphics - Coarse Scale Fill Color: 0
Type - Identity Data - Type Image: Raster image: Naturoll 037.jpg (3); Assembly Code: 21; Assembly Description: Buitenwanden; Description: Naturoll 037 - 90mm; Manufacturer: Knauf Insulation B.V.; Model: Naturoll 037 is een onbeklede glaswoldeken met ECOSE® Technology; Type Name: NLRS_21_WA_Naturoll 037_90x380x8200mm; URL: www.knaufinsulation.nl
Type - Other - Category: Walls; Family Name: Basic Wall
Type - Pset_ElementShading - Roughness: 304.8 mm
Type - Pset_ManufacturerTypeInformation - Manufacturer: Knauf Insulation B.V.
Type - Pset_ProductRequirements - Category: Walls
Type - Pset_QuantityTakeOff - Reference: NLRS_21_WA_Naturoll 037_90x380x8200mm
Type - Pset_ReinforcementBarPitchOfWall - Description: Naturoll 037 - 90mm; Reference: NLRS_21_WA_Naturoll 037_90x380x8200mm
Type - Pset_WallCommon - IsExternal: no; Reference: NLRS_21_WA_Naturoll 037_90x380x8200mm; ThermalTransmittance: 0.388889 kg/K/s3
Classification: 21 Buitenwanden (Uniformat)
BaseQuantities - Height: 2500 mm; Width: 90 mm
Constraints - Related to Mass: no; Room Bounding: yes; Base Constraint: Level: Begane grond; Base Extension Distance: 0 mm; Base is Attached: no; Base Offset: 0 mm; Top Constraint: Level: Lengte; Top Extension Distance: 0 mm; Top is Attached: no; Top Offset: 0 mm; Unconnected Height: 2500 mm
Other - Family: Basic Wall: NLRS_21_WA_Naturoll 037_90x380x8200mm; Family and Type: Basic Wall: NLRS_21_WA_Naturoll 037_90x380x8200mm; Type: Basic Wall: NLRS_21_WA_Naturoll 037_90x380x8200mm; Type Id: Basic Wall: NLRS_21_WA_Naturoll 037_90x380x8200mm
Phasing - Phase Created: New Construction
Structural - Enable Analytical Model: no; Structural: no; Structural Usage: Non-bearing
Pset_WallCommon - LoadBearing: no; IsExternal: yes; ExtendToStructure: no
Name (Basic Wall:NLRS_21_WA_Naturoll 037_90x380x8200mm:...) | BaseQuantities, Length (mm) = Dimensions, Length (mm) | GrossFootprintArea (m2) | NetVolume (m3) | NetSideArea (m2) | Location Line | Area (m2) | Volume (m3)
11658 | 2000 | 0.18 | 450000000 | 5000000 | Core Face: Interior | 5 | 0.45
11746 | 500 | 0.045 | 112500000 | 1250000 | Wall Centerline | 1.25 | 0.1125

# IfcWallStandardCase: Basic Wall:NLRS_21_WA_Naturoll 037_90x580x8200mm (2)
In: Begane grond
Type - PredefinedType: STANDARD; Material: Knauf Insulation_Ecose® glaswol_naturoll 037 90 mm
Type - Analytical Properties - Roughness: 1; Thermal mass: 0; Absorptance: 0.1; Heat Transfer Coefficient (U): 0.388889; Thermal Resistance (R): 2.57143
Type - Construction - Function: Exterior; Wrapping at Inserts: Do not wrap; Width: 90 mm
Type - Graphics - Coarse Scale Fill Color: 0
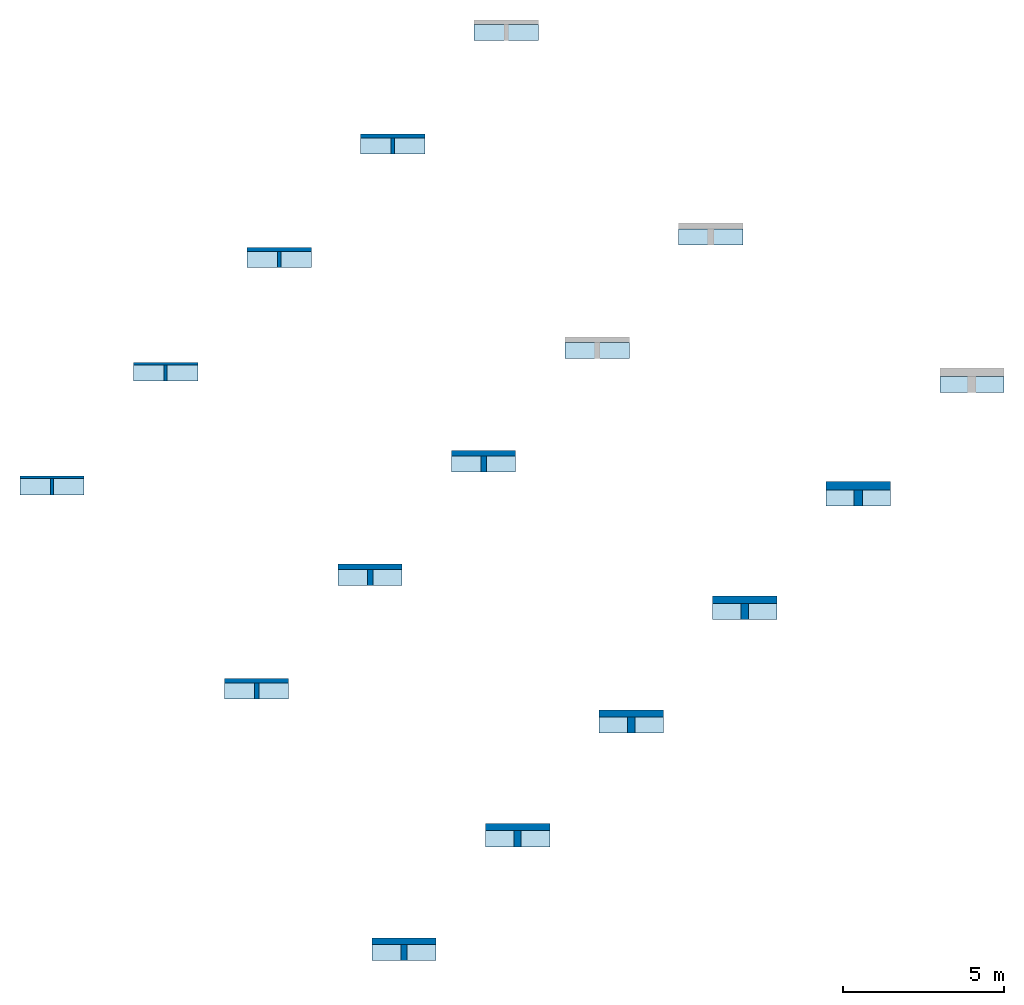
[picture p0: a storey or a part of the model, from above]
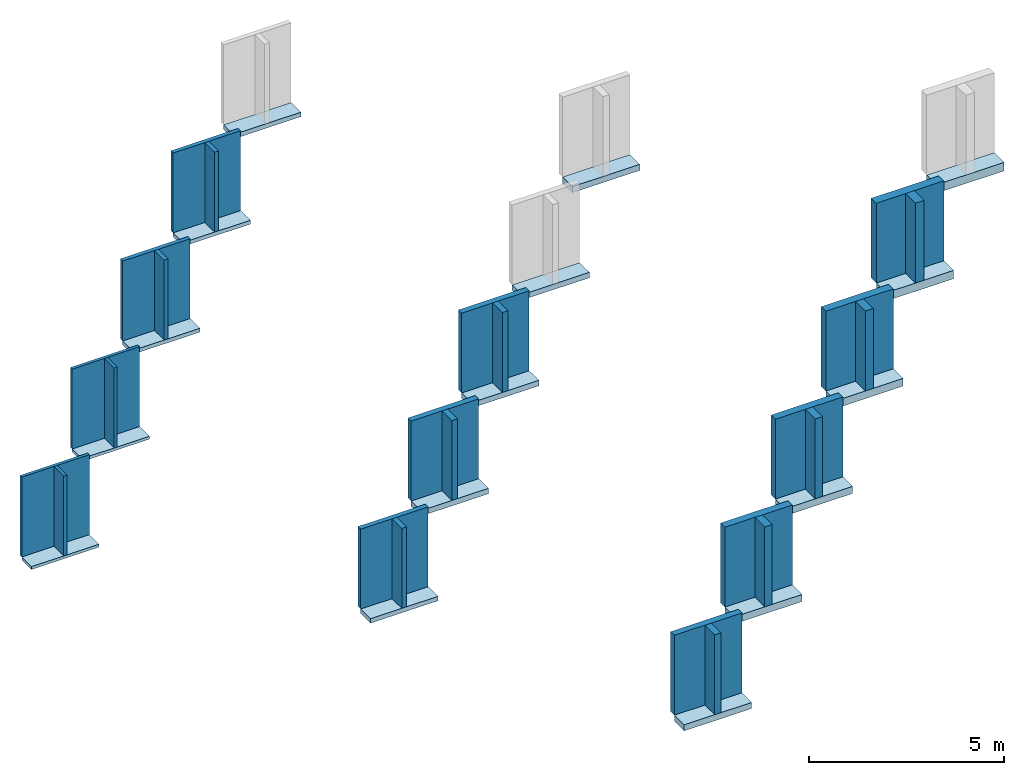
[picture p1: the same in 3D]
Properties of the parts of a building model (IFC2X3), part 3 of 3

# IfcWallStandardCase: Basic Wall:NLRS_21_WA_Naturoll 037_90x580x8200mm (2)
Type - Identity Data - Type Image: Raster image: Naturoll 037.jpg (3); Assembly Code: 21; Assembly Description: Buitenwanden; Description: Naturoll 037 - 90mm; Manufacturer: Knauf Insulation B.V.; Model: Naturoll 037 is een onbeklede glaswoldeken met ECOSE® Technology; Type Name: NLRS_21_WA_Naturoll 037_90x580x8200mm; URL: www.knaufinsulation.nl
Type - Other - Category: Walls; Family Name: Basic Wall
Type - Pset_ElementShading - Roughness: 304.8 mm
Type - Pset_ManufacturerTypeInformation - Manufacturer: Knauf Insulation B.V.
Type - Pset_ProductRequirements - Category: Walls
Type - Pset_QuantityTakeOff - Reference: NLRS_21_WA_Naturoll 037_90x580x8200mm
Type - Pset_ReinforcementBarPitchOfWall - Description: Naturoll 037 - 90mm; Reference: NLRS_21_WA_Naturoll 037_90x580x8200mm
Type - Pset_WallCommon - IsExternal: no; Reference: NLRS_21_WA_Naturoll 037_90x580x8200mm; ThermalTransmittance: 0.388889 kg/K/s3
Classification: 21 Buitenwanden (Uniformat)
BaseQuantities - Height: 2500 mm; Width: 90 mm
Constraints - Related to Mass: no; Room Bounding: yes; Base Constraint: Level: Begane grond; Base Extension Distance: 0 mm; Base is Attached: no; Base Offset: 0 mm; Top Constraint: Level: Lengte; Top Extension Distance: 0 mm; Top is Attached: no; Top Offset: 0 mm; Unconnected Height: 2500 mm
Other - Family: Basic Wall: NLRS_21_WA_Naturoll 037_90x580x8200mm; Family and Type: Basic Wall: NLRS_21_WA_Naturoll 037_90x580x8200mm; Type: Basic Wall: NLRS_21_WA_Naturoll 037_90x580x8200mm; Type Id: Basic Wall: NLRS_21_WA_Naturoll 037_90x580x8200mm
Phasing - Phase Created: New Construction
Structural - Enable Analytical Model: no; Structural: no; Structural Usage: Non-bearing
Pset_WallCommon - LoadBearing: no; IsExternal: yes; ExtendToStructure: no
Name (Basic Wall:NLRS_21_WA_Naturoll 037_90x580x8200mm:...) | BaseQuantities, Length (mm) = Dimensions, Length (mm) | GrossFootprintArea (m2) | NetVolume (m3) | NetSideArea (m2) | Location Line | Area (m2) | Volume (m3)
12982 | 2000 | 0.18 | 450000000 | 5000000 | Core Face: Interior | 5 | 0.45
12984 | 500 | 0.045 | 112500000 | 1250000 | Wall Centerline | 1.25 | 0.1125
